VERSION 5.7 ;
DIVIDERCHAR "/" ;
BUSBITCHARS "[]" ;

VERSION 5.7 ;

BUSBITCHARS "[]" ;
DIVIDERCHAR "/" ;

UNITS
  TIME NANOSECONDS 1 ;
  CAPACITANCE PICOFARADS 1 ;
  RESISTANCE OHMS 1 ;
  DATABASE MICRONS 1000 ;
END UNITS

MANUFACTURINGGRID 0.005 ;

PROPERTYDEFINITIONS
  LAYER LEF58_TYPE STRING ;
END PROPERTYDEFINITIONS

# High density, single height
SITE obssite
  SYMMETRY Y ;
  CLASS CORE ;
  SIZE 0.56 BY 7.84 ;
END obssite


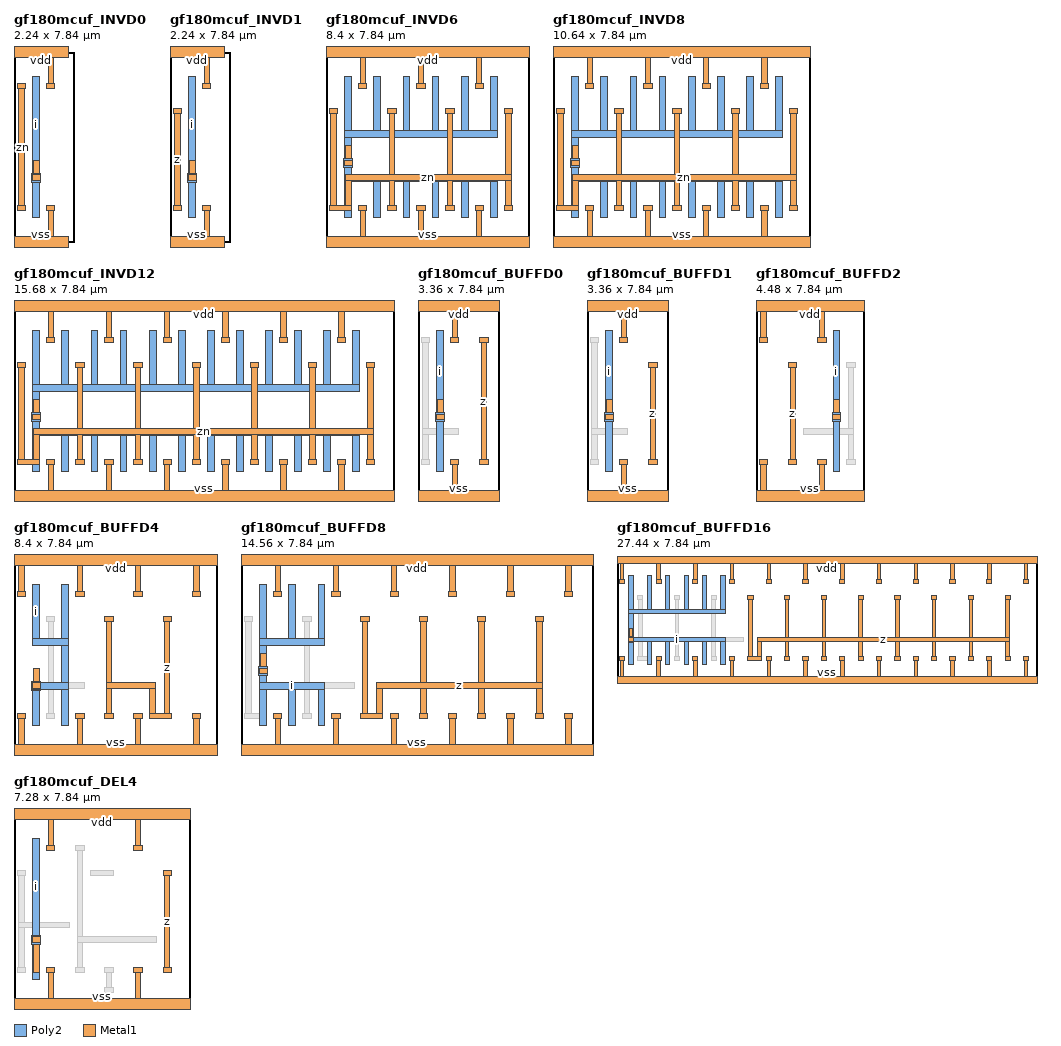
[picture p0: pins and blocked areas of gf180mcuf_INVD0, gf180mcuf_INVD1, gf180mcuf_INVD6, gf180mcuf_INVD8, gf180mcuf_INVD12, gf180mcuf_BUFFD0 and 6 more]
MACRO gf180mcuf_INVD0
  CLASS CORE ;
  FOREIGN gf180mcuf_INVD0 ;
  ORIGIN 0.000 0.000 ;
  SIZE 2.240 BY 7.840 ;
  SYMMETRY X Y R90 ;
  SITE obssite ;
  PIN i
    DIRECTION INPUT ;
    USE SIGNAL ;
    ANTENNAGATEAREA 0.308000 ;
    PORT
      LAYER Poly2 ;
        RECT 0.780 0.995 1.060 2.475 ;
        RECT 0.740 2.475 1.100 2.835 ;
        RECT 0.780 2.835 1.060 6.845 ;
      LAYER Metal1 ;
        RECT 0.750 2.540 1.090 2.770 ;
        RECT 0.805 2.770 1.035 3.370 ;
    END
  END i
  PIN vdd
    DIRECTION INOUT ;
    USE POWER ;
    SHAPE ABUTMENT ;
    PORT
      LAYER Metal1 ;
        RECT 1.350 6.330 1.690 6.560 ;
        RECT 1.405 6.560 1.635 7.610 ;
        RECT 0.000 7.610 2.240 8.070 ;
    END
  END vdd
  PIN vss
    DIRECTION INOUT ;
    USE GROUND ;
    SHAPE ABUTMENT ;
    PORT
      LAYER Metal1 ;
        RECT 0.000 -0.230 2.240 0.230 ;
        RECT 1.405 0.230 1.635 1.280 ;
        RECT 1.350 1.280 1.690 1.510 ;
    END
  END vss
  PIN zn
    DIRECTION OUTPUT ;
    USE SIGNAL ;
    ANTENNADIFFAREA 0.704000 ;
    PORT
      LAYER Metal1 ;
        RECT 0.150 1.280 0.490 1.510 ;
        RECT 0.205 1.510 0.435 6.330 ;
        RECT 0.150 6.330 0.490 6.560 ;
    END
  END zn
END gf180mcuf_INVD0

MACRO gf180mcuf_INVD1
  CLASS CORE ;
  FOREIGN gf180mcuf_INVD1 ;
  ORIGIN 0.000 0.000 ;
  SIZE 2.240 BY 7.840 ;
  SYMMETRY X Y R90 ;
  SITE obssite ;
  PIN z
    DIRECTION OUTPUT ;
    USE SIGNAL ;
    ANTENNADIFFAREA 1.408000 ;
    PORT
      LAYER Metal1 ;
        RECT 0.150 1.280 0.490 1.510 ;
        RECT 0.205 1.510 0.435 5.290 ;
        RECT 0.150 5.290 0.490 5.520 ;
    END
  END z
  PIN vdd
    DIRECTION INOUT ;
    USE POWER ;
    SHAPE ABUTMENT ;
    PORT
      LAYER Metal1 ;
        RECT 1.350 6.330 1.690 6.560 ;
        RECT 1.405 6.560 1.635 7.610 ;
        RECT 0.000 7.610 2.240 8.070 ;
    END
  END vdd
  PIN vss
    DIRECTION INOUT ;
    USE GROUND ;
    SHAPE ABUTMENT ;
    PORT
      LAYER Metal1 ;
        RECT 0.000 -0.230 2.240 0.230 ;
        RECT 1.405 0.230 1.635 1.280 ;
        RECT 1.350 1.280 1.690 1.510 ;
    END
  END vss
  PIN i
    DIRECTION INPUT ;
    USE SIGNAL ;
    ANTENNAGATEAREA 0.616000 ;
    PORT
      LAYER Poly2 ;
        RECT 0.780 0.995 1.060 2.475 ;
        RECT 0.740 2.475 1.100 2.835 ;
        RECT 0.780 2.835 1.060 6.845 ;
      LAYER Metal1 ;
        RECT 0.750 2.540 1.090 2.770 ;
        RECT 0.805 2.770 1.035 3.370 ;
    END
  END i
END gf180mcuf_INVD1

MACRO gf180mcuf_INVD6
  CLASS CORE ;
  FOREIGN gf180mcuf_INVD6 ;
  ORIGIN 0.000 0.000 ;
  SIZE 8.400 BY 7.840 ;
  SYMMETRY X Y R90 ;
  SITE obssite ;
  PIN i
    DIRECTION INPUT ;
    USE SIGNAL ;
    ANTENNAGATEAREA 3.696000 ;
    PORT
      LAYER Poly2 ;
        RECT 0.780 0.995 1.060 2.515 ;
        RECT 1.980 0.995 2.260 2.515 ;
        RECT 3.180 0.995 3.460 2.515 ;
        RECT 4.380 0.995 4.660 2.515 ;
        RECT 5.580 0.995 5.860 2.515 ;
        RECT 6.780 0.995 7.060 2.515 ;
        RECT 0.780 2.515 7.060 2.795 ;
        RECT 0.780 2.795 1.060 3.075 ;
        RECT 0.740 3.075 1.100 3.435 ;
        RECT 0.780 3.435 1.060 4.315 ;
        RECT 0.780 4.315 7.060 4.595 ;
        RECT 0.780 4.595 1.060 6.845 ;
        RECT 1.980 4.595 2.260 6.845 ;
        RECT 3.180 4.595 3.460 6.845 ;
        RECT 4.380 4.595 4.660 6.845 ;
        RECT 5.580 4.595 5.860 6.845 ;
        RECT 6.780 4.595 7.060 6.845 ;
      LAYER Metal1 ;
        RECT 0.750 3.140 1.090 3.370 ;
        RECT 0.805 3.370 1.035 3.970 ;
    END
  END i
  PIN vdd
    DIRECTION INOUT ;
    USE POWER ;
    SHAPE ABUTMENT ;
    PORT
      LAYER Metal1 ;
        RECT 1.350 6.330 1.690 6.560 ;
        RECT 3.750 6.330 4.090 6.560 ;
        RECT 6.150 6.330 6.490 6.560 ;
        RECT 1.405 6.560 1.635 7.610 ;
        RECT 3.805 6.560 4.035 7.610 ;
        RECT 6.205 6.560 6.435 7.610 ;
        RECT 0.000 7.610 8.400 8.070 ;
    END
  END vdd
  PIN vss
    DIRECTION INOUT ;
    USE GROUND ;
    SHAPE ABUTMENT ;
    PORT
      LAYER Metal1 ;
        RECT 0.000 -0.230 8.400 0.230 ;
        RECT 1.405 0.230 1.635 1.280 ;
        RECT 3.805 0.230 4.035 1.280 ;
        RECT 6.205 0.230 6.435 1.280 ;
        RECT 1.350 1.280 1.690 1.510 ;
        RECT 3.750 1.280 4.090 1.510 ;
        RECT 6.150 1.280 6.490 1.510 ;
    END
  END vss
  PIN zn
    DIRECTION OUTPUT ;
    USE SIGNAL ;
    ANTENNADIFFAREA 6.864000 ;
    PORT
      LAYER Metal1 ;
        RECT 0.150 1.280 1.035 1.510 ;
        RECT 2.550 1.280 2.890 1.510 ;
        RECT 4.950 1.280 5.290 1.510 ;
        RECT 7.350 1.280 7.690 1.510 ;
        RECT 0.205 1.510 0.435 5.290 ;
        RECT 0.805 1.510 1.035 2.540 ;
        RECT 2.605 1.510 2.835 2.540 ;
        RECT 5.005 1.510 5.235 2.540 ;
        RECT 7.405 1.510 7.635 2.540 ;
        RECT 0.805 2.540 7.635 2.770 ;
        RECT 2.605 2.770 2.835 5.290 ;
        RECT 5.005 2.770 5.235 5.290 ;
        RECT 7.405 2.770 7.635 5.290 ;
        RECT 0.150 5.290 0.490 5.520 ;
        RECT 2.550 5.290 2.890 5.520 ;
        RECT 4.950 5.290 5.290 5.520 ;
        RECT 7.350 5.290 7.690 5.520 ;
    END
  END zn
END gf180mcuf_INVD6

MACRO gf180mcuf_INVD8
  CLASS CORE ;
  FOREIGN gf180mcuf_INVD8 ;
  ORIGIN 0.000 0.000 ;
  SIZE 10.640 BY 7.840 ;
  SYMMETRY X Y R90 ;
  SITE obssite ;
  PIN i
    DIRECTION INPUT ;
    USE SIGNAL ;
    ANTENNAGATEAREA 4.928000 ;
    PORT
      LAYER Poly2 ;
        RECT 0.780 0.995 1.060 2.515 ;
        RECT 1.980 0.995 2.260 2.515 ;
        RECT 3.180 0.995 3.460 2.515 ;
        RECT 4.380 0.995 4.660 2.515 ;
        RECT 5.580 0.995 5.860 2.515 ;
        RECT 6.780 0.995 7.060 2.515 ;
        RECT 7.980 0.995 8.260 2.515 ;
        RECT 9.180 0.995 9.460 2.515 ;
        RECT 0.780 2.515 9.460 2.795 ;
        RECT 0.780 2.795 1.060 3.075 ;
        RECT 0.740 3.075 1.100 3.435 ;
        RECT 0.780 3.435 1.060 4.315 ;
        RECT 0.780 4.315 9.460 4.595 ;
        RECT 0.780 4.595 1.060 6.845 ;
        RECT 1.980 4.595 2.260 6.845 ;
        RECT 3.180 4.595 3.460 6.845 ;
        RECT 4.380 4.595 4.660 6.845 ;
        RECT 5.580 4.595 5.860 6.845 ;
        RECT 6.780 4.595 7.060 6.845 ;
        RECT 7.980 4.595 8.260 6.845 ;
        RECT 9.180 4.595 9.460 6.845 ;
      LAYER Metal1 ;
        RECT 0.750 3.140 1.090 3.370 ;
        RECT 0.805 3.370 1.035 3.970 ;
    END
  END i
  PIN vdd
    DIRECTION INOUT ;
    USE POWER ;
    SHAPE ABUTMENT ;
    PORT
      LAYER Metal1 ;
        RECT 1.350 6.330 1.690 6.560 ;
        RECT 3.750 6.330 4.090 6.560 ;
        RECT 6.150 6.330 6.490 6.560 ;
        RECT 8.550 6.330 8.890 6.560 ;
        RECT 1.405 6.560 1.635 7.610 ;
        RECT 3.805 6.560 4.035 7.610 ;
        RECT 6.205 6.560 6.435 7.610 ;
        RECT 8.605 6.560 8.835 7.610 ;
        RECT 0.000 7.610 10.640 8.070 ;
    END
  END vdd
  PIN vss
    DIRECTION INOUT ;
    USE GROUND ;
    SHAPE ABUTMENT ;
    PORT
      LAYER Metal1 ;
        RECT 0.000 -0.230 10.640 0.230 ;
        RECT 1.405 0.230 1.635 1.280 ;
        RECT 3.805 0.230 4.035 1.280 ;
        RECT 6.205 0.230 6.435 1.280 ;
        RECT 8.605 0.230 8.835 1.280 ;
        RECT 1.350 1.280 1.690 1.510 ;
        RECT 3.750 1.280 4.090 1.510 ;
        RECT 6.150 1.280 6.490 1.510 ;
        RECT 8.550 1.280 8.890 1.510 ;
    END
  END vss
  PIN zn
    DIRECTION OUTPUT ;
    USE SIGNAL ;
    ANTENNADIFFAREA 8.888000 ;
    PORT
      LAYER Metal1 ;
        RECT 0.150 1.280 1.035 1.510 ;
        RECT 2.550 1.280 2.890 1.510 ;
        RECT 4.950 1.280 5.290 1.510 ;
        RECT 7.350 1.280 7.690 1.510 ;
        RECT 9.750 1.280 10.090 1.510 ;
        RECT 0.205 1.510 0.435 5.290 ;
        RECT 0.805 1.510 1.035 2.540 ;
        RECT 2.605 1.510 2.835 2.540 ;
        RECT 5.005 1.510 5.235 2.540 ;
        RECT 7.405 1.510 7.635 2.540 ;
        RECT 9.805 1.510 10.035 2.540 ;
        RECT 0.805 2.540 10.035 2.770 ;
        RECT 2.605 2.770 2.835 5.290 ;
        RECT 5.005 2.770 5.235 5.290 ;
        RECT 7.405 2.770 7.635 5.290 ;
        RECT 9.805 2.770 10.035 5.290 ;
        RECT 0.150 5.290 0.490 5.520 ;
        RECT 2.550 5.290 2.890 5.520 ;
        RECT 4.950 5.290 5.290 5.520 ;
        RECT 7.350 5.290 7.690 5.520 ;
        RECT 9.750 5.290 10.090 5.520 ;
    END
  END zn
END gf180mcuf_INVD8

MACRO gf180mcuf_INVD12
  CLASS CORE ;
  FOREIGN gf180mcuf_INVD12 ;
  ORIGIN 0.000 0.000 ;
  SIZE 15.680 BY 7.840 ;
  SYMMETRY X Y R90 ;
  SITE obssite ;
  PIN i
    DIRECTION INPUT ;
    USE SIGNAL ;
    ANTENNAGATEAREA 7.392000 ;
    PORT
      LAYER Poly2 ;
        RECT 0.780 0.995 1.060 2.515 ;
        RECT 1.980 0.995 2.260 2.515 ;
        RECT 3.180 0.995 3.460 2.515 ;
        RECT 4.380 0.995 4.660 2.515 ;
        RECT 5.580 0.995 5.860 2.515 ;
        RECT 6.780 0.995 7.060 2.515 ;
        RECT 7.980 0.995 8.260 2.515 ;
        RECT 9.180 0.995 9.460 2.515 ;
        RECT 10.380 0.995 10.660 2.515 ;
        RECT 11.580 0.995 11.860 2.515 ;
        RECT 12.780 0.995 13.060 2.515 ;
        RECT 13.980 0.995 14.260 2.515 ;
        RECT 0.780 2.515 14.260 2.795 ;
        RECT 0.780 2.795 1.060 3.075 ;
        RECT 0.740 3.075 1.100 3.435 ;
        RECT 0.780 3.435 1.060 4.315 ;
        RECT 0.780 4.315 14.260 4.595 ;
        RECT 0.780 4.595 1.060 6.845 ;
        RECT 1.980 4.595 2.260 6.845 ;
        RECT 3.180 4.595 3.460 6.845 ;
        RECT 4.380 4.595 4.660 6.845 ;
        RECT 5.580 4.595 5.860 6.845 ;
        RECT 6.780 4.595 7.060 6.845 ;
        RECT 7.980 4.595 8.260 6.845 ;
        RECT 9.180 4.595 9.460 6.845 ;
        RECT 10.380 4.595 10.660 6.845 ;
        RECT 11.580 4.595 11.860 6.845 ;
        RECT 12.780 4.595 13.060 6.845 ;
        RECT 13.980 4.595 14.260 6.845 ;
      LAYER Metal1 ;
        RECT 0.750 3.140 1.090 3.370 ;
        RECT 0.805 3.370 1.035 3.970 ;
    END
  END i
  PIN vdd
    DIRECTION INOUT ;
    USE POWER ;
    SHAPE ABUTMENT ;
    PORT
      LAYER Metal1 ;
        RECT 1.350 6.330 1.690 6.560 ;
        RECT 3.750 6.330 4.090 6.560 ;
        RECT 6.150 6.330 6.490 6.560 ;
        RECT 8.550 6.330 8.890 6.560 ;
        RECT 10.950 6.330 11.290 6.560 ;
        RECT 13.350 6.330 13.690 6.560 ;
        RECT 1.405 6.560 1.635 7.610 ;
        RECT 3.805 6.560 4.035 7.610 ;
        RECT 6.205 6.560 6.435 7.610 ;
        RECT 8.605 6.560 8.835 7.610 ;
        RECT 11.005 6.560 11.235 7.610 ;
        RECT 13.405 6.560 13.635 7.610 ;
        RECT 0.000 7.610 15.680 8.070 ;
    END
  END vdd
  PIN vss
    DIRECTION INOUT ;
    USE GROUND ;
    SHAPE ABUTMENT ;
    PORT
      LAYER Metal1 ;
        RECT 0.000 -0.230 15.680 0.230 ;
        RECT 1.405 0.230 1.635 1.280 ;
        RECT 3.805 0.230 4.035 1.280 ;
        RECT 6.205 0.230 6.435 1.280 ;
        RECT 8.605 0.230 8.835 1.280 ;
        RECT 11.005 0.230 11.235 1.280 ;
        RECT 13.405 0.230 13.635 1.280 ;
        RECT 1.350 1.280 1.690 1.510 ;
        RECT 3.750 1.280 4.090 1.510 ;
        RECT 6.150 1.280 6.490 1.510 ;
        RECT 8.550 1.280 8.890 1.510 ;
        RECT 10.950 1.280 11.290 1.510 ;
        RECT 13.350 1.280 13.690 1.510 ;
    END
  END vss
  PIN zn
    DIRECTION OUTPUT ;
    USE SIGNAL ;
    ANTENNADIFFAREA 12.936000 ;
    PORT
      LAYER Metal1 ;
        RECT 0.150 1.280 1.035 1.510 ;
        RECT 2.550 1.280 2.890 1.510 ;
        RECT 4.950 1.280 5.290 1.510 ;
        RECT 7.350 1.280 7.690 1.510 ;
        RECT 9.750 1.280 10.090 1.510 ;
        RECT 12.150 1.280 12.490 1.510 ;
        RECT 14.550 1.280 14.890 1.510 ;
        RECT 0.205 1.510 0.435 5.290 ;
        RECT 0.805 1.510 1.035 2.540 ;
        RECT 2.605 1.510 2.835 2.540 ;
        RECT 5.005 1.510 5.235 2.540 ;
        RECT 7.405 1.510 7.635 2.540 ;
        RECT 9.805 1.510 10.035 2.540 ;
        RECT 12.205 1.510 12.435 2.540 ;
        RECT 14.605 1.510 14.835 2.540 ;
        RECT 0.805 2.540 14.835 2.770 ;
        RECT 2.605 2.770 2.835 5.290 ;
        RECT 5.005 2.770 5.235 5.290 ;
        RECT 7.405 2.770 7.635 5.290 ;
        RECT 9.805 2.770 10.035 5.290 ;
        RECT 12.205 2.770 12.435 5.290 ;
        RECT 14.605 2.770 14.835 5.290 ;
        RECT 0.150 5.290 0.490 5.520 ;
        RECT 2.550 5.290 2.890 5.520 ;
        RECT 4.950 5.290 5.290 5.520 ;
        RECT 7.350 5.290 7.690 5.520 ;
        RECT 9.750 5.290 10.090 5.520 ;
        RECT 12.150 5.290 12.490 5.520 ;
        RECT 14.550 5.290 14.890 5.520 ;
    END
  END zn
END gf180mcuf_INVD12

MACRO gf180mcuf_BUFFD0
  CLASS CORE ;
  FOREIGN gf180mcuf_BUFFD0 ;
  ORIGIN 0.000 0.000 ;
  SIZE 3.360 BY 7.840 ;
  SYMMETRY X Y R90 ;
  SITE obssite ;
  PIN i
    DIRECTION INPUT ;
    USE SIGNAL ;
    ANTENNAGATEAREA 0.193200 ;
    PORT
      LAYER Poly2 ;
        RECT 0.780 0.995 1.060 3.075 ;
        RECT 0.740 3.075 1.100 3.435 ;
        RECT 0.780 3.435 1.060 6.845 ;
      LAYER Metal1 ;
        RECT 0.750 3.140 1.090 3.370 ;
        RECT 0.805 3.370 1.035 3.970 ;
    END
  END i
  PIN vdd
    DIRECTION INOUT ;
    USE POWER ;
    SHAPE ABUTMENT ;
    PORT
      LAYER Metal1 ;
        RECT 1.350 6.330 1.690 6.560 ;
        RECT 1.405 6.560 1.635 7.610 ;
        RECT 0.000 7.610 3.360 8.070 ;
    END
  END vdd
  PIN vss
    DIRECTION INOUT ;
    USE GROUND ;
    SHAPE ABUTMENT ;
    PORT
      LAYER Metal1 ;
        RECT 0.000 -0.230 3.360 0.230 ;
        RECT 1.405 0.230 1.635 1.280 ;
        RECT 1.350 1.280 1.690 1.510 ;
    END
  END vss
  PIN z
    DIRECTION OUTPUT ;
    USE SIGNAL ;
    ANTENNADIFFAREA 0.646400 ;
    PORT
      LAYER Metal1 ;
        RECT 2.550 1.280 2.890 1.510 ;
        RECT 2.605 1.510 2.835 6.330 ;
        RECT 2.550 6.330 2.890 6.560 ;
    END
  END z
  OBS
    LAYER Metal1 ;
      RECT 0.150 1.280 0.490 1.510 ;
      RECT 0.205 1.510 0.435 2.540 ;
      RECT 0.205 2.540 1.690 2.770 ;
      RECT 0.205 2.770 0.435 6.330 ;
      RECT 0.150 6.330 0.490 6.560 ;
  END
END gf180mcuf_BUFFD0

MACRO gf180mcuf_BUFFD1
  CLASS CORE ;
  FOREIGN gf180mcuf_BUFFD1 ;
  ORIGIN 0.000 0.000 ;
  SIZE 3.360 BY 7.840 ;
  SYMMETRY X Y R90 ;
  SITE obssite ;
  PIN i
    DIRECTION INPUT ;
    USE SIGNAL ;
    ANTENNAGATEAREA 0.308000 ;
    PORT
      LAYER Poly2 ;
        RECT 0.780 0.995 1.060 3.075 ;
        RECT 0.740 3.075 1.100 3.435 ;
        RECT 0.780 3.435 1.060 6.845 ;
      LAYER Metal1 ;
        RECT 0.750 3.140 1.090 3.370 ;
        RECT 0.805 3.370 1.035 3.970 ;
    END
  END i
  PIN vdd
    DIRECTION INOUT ;
    USE POWER ;
    SHAPE ABUTMENT ;
    PORT
      LAYER Metal1 ;
        RECT 1.350 6.330 1.690 6.560 ;
        RECT 1.405 6.560 1.635 7.610 ;
        RECT 0.000 7.610 3.360 8.070 ;
    END
  END vdd
  PIN vss
    DIRECTION INOUT ;
    USE GROUND ;
    SHAPE ABUTMENT ;
    PORT
      LAYER Metal1 ;
        RECT 0.000 -0.230 3.360 0.230 ;
        RECT 1.405 0.230 1.635 1.280 ;
        RECT 1.350 1.280 1.690 1.510 ;
    END
  END vss
  PIN z
    DIRECTION OUTPUT ;
    USE SIGNAL ;
    ANTENNADIFFAREA 1.408000 ;
    PORT
      LAYER Metal1 ;
        RECT 2.550 1.280 2.890 1.510 ;
        RECT 2.605 1.510 2.835 5.290 ;
        RECT 2.550 5.290 2.890 5.520 ;
    END
  END z
  OBS
    LAYER Metal1 ;
      RECT 0.150 1.280 0.490 1.510 ;
      RECT 0.205 1.510 0.435 2.540 ;
      RECT 0.205 2.540 1.690 2.770 ;
      RECT 0.205 2.770 0.435 6.330 ;
      RECT 0.150 6.330 0.490 6.560 ;
  END
END gf180mcuf_BUFFD1

MACRO gf180mcuf_BUFFD2
  CLASS CORE ;
  FOREIGN gf180mcuf_BUFFD2 ;
  ORIGIN 0.000 0.000 ;
  SIZE 4.480 BY 7.840 ;
  SYMMETRY X Y R90 ;
  SITE obssite ;
  PIN i
    DIRECTION INPUT ;
    USE SIGNAL ;
    ANTENNAGATEAREA 0.616000 ;
    PORT
      LAYER Poly2 ;
        RECT 3.180 0.995 3.460 3.075 ;
        RECT 3.140 3.075 3.500 3.435 ;
        RECT 3.180 3.435 3.460 6.845 ;
      LAYER Metal1 ;
        RECT 3.150 3.140 3.490 3.370 ;
        RECT 3.205 3.370 3.435 3.970 ;
    END
  END i
  PIN vdd
    DIRECTION INOUT ;
    USE POWER ;
    SHAPE ABUTMENT ;
    PORT
      LAYER Metal1 ;
        RECT 0.150 6.330 0.490 6.560 ;
        RECT 2.550 6.330 2.890 6.560 ;
        RECT 0.205 6.560 0.435 7.610 ;
        RECT 2.605 6.560 2.835 7.610 ;
        RECT 0.000 7.610 4.480 8.070 ;
    END
  END vdd
  PIN vss
    DIRECTION INOUT ;
    USE GROUND ;
    SHAPE ABUTMENT ;
    PORT
      LAYER Metal1 ;
        RECT 0.000 -0.230 4.480 0.230 ;
        RECT 0.205 0.230 0.435 1.280 ;
        RECT 2.605 0.230 2.835 1.280 ;
        RECT 0.150 1.280 0.490 1.510 ;
        RECT 2.550 1.280 2.890 1.510 ;
    END
  END vss
  PIN z
    DIRECTION OUTPUT ;
    USE SIGNAL ;
    ANTENNADIFFAREA 2.024000 ;
    PORT
      LAYER Metal1 ;
        RECT 1.350 1.280 1.690 1.510 ;
        RECT 1.405 1.510 1.635 5.290 ;
        RECT 1.350 5.290 1.690 5.520 ;
    END
  END z
  OBS
    LAYER Metal1 ;
      RECT 3.750 1.280 4.090 1.510 ;
      RECT 3.805 1.510 4.035 2.540 ;
      RECT 1.950 2.540 4.035 2.770 ;
      RECT 3.805 2.770 4.035 5.290 ;
      RECT 3.750 5.290 4.090 5.520 ;
  END
END gf180mcuf_BUFFD2

MACRO gf180mcuf_BUFFD4
  CLASS CORE ;
  FOREIGN gf180mcuf_BUFFD4 ;
  ORIGIN 0.000 0.000 ;
  SIZE 8.400 BY 7.840 ;
  SYMMETRY X Y R90 ;
  SITE obssite ;
  PIN i
    DIRECTION INPUT ;
    USE SIGNAL ;
    ANTENNAGATEAREA 1.232000 ;
    PORT
      LAYER Poly2 ;
        RECT 0.780 0.995 1.060 2.475 ;
        RECT 1.980 0.995 2.260 2.515 ;
        RECT 0.740 2.475 1.100 2.515 ;
        RECT 0.740 2.515 2.260 2.795 ;
        RECT 0.740 2.795 1.100 2.835 ;
        RECT 1.980 2.795 2.260 4.315 ;
        RECT 0.780 4.315 2.260 4.595 ;
        RECT 0.780 4.595 1.060 6.845 ;
        RECT 1.980 4.595 2.260 6.845 ;
      LAYER Metal1 ;
        RECT 0.750 2.540 1.090 2.770 ;
        RECT 0.805 2.770 1.035 3.370 ;
    END
  END i
  PIN vdd
    DIRECTION INOUT ;
    USE POWER ;
    SHAPE ABUTMENT ;
    PORT
      LAYER Metal1 ;
        RECT 0.150 6.330 0.490 6.560 ;
        RECT 2.550 6.330 2.890 6.560 ;
        RECT 4.950 6.330 5.290 6.560 ;
        RECT 7.350 6.330 7.690 6.560 ;
        RECT 0.205 6.560 0.435 7.610 ;
        RECT 2.605 6.560 2.835 7.610 ;
        RECT 5.005 6.560 5.235 7.610 ;
        RECT 7.405 6.560 7.635 7.610 ;
        RECT 0.000 7.610 8.400 8.070 ;
    END
  END vdd
  PIN vss
    DIRECTION INOUT ;
    USE GROUND ;
    SHAPE ABUTMENT ;
    PORT
      LAYER Metal1 ;
        RECT 0.000 -0.230 8.400 0.230 ;
        RECT 0.205 0.230 0.435 1.280 ;
        RECT 2.605 0.230 2.835 1.280 ;
        RECT 5.005 0.230 5.235 1.280 ;
        RECT 7.405 0.230 7.635 1.280 ;
        RECT 0.150 1.280 0.490 1.510 ;
        RECT 2.550 1.280 2.890 1.510 ;
        RECT 4.950 1.280 5.290 1.510 ;
        RECT 7.350 1.280 7.690 1.510 ;
    END
  END vss
  PIN z
    DIRECTION OUTPUT ;
    USE SIGNAL ;
    ANTENNADIFFAREA 4.048000 ;
    PORT
      LAYER Metal1 ;
        RECT 3.750 1.280 4.090 1.510 ;
        RECT 5.605 1.280 6.490 1.510 ;
        RECT 3.805 1.510 4.035 2.540 ;
        RECT 5.605 1.510 5.835 2.540 ;
        RECT 6.205 1.510 6.435 5.290 ;
        RECT 3.805 2.540 5.835 2.770 ;
        RECT 3.805 2.770 4.035 5.290 ;
        RECT 3.750 5.290 4.090 5.520 ;
        RECT 6.150 5.290 6.490 5.520 ;
    END
  END z
  OBS
    LAYER Metal1 ;
      RECT 1.350 1.280 1.690 1.510 ;
      RECT 1.405 1.510 1.635 2.540 ;
      RECT 1.405 2.540 2.890 2.770 ;
      RECT 1.405 2.770 1.635 5.290 ;
      RECT 1.350 5.290 1.690 5.520 ;
  END
END gf180mcuf_BUFFD4

MACRO gf180mcuf_BUFFD8
  CLASS CORE ;
  FOREIGN gf180mcuf_BUFFD8 ;
  ORIGIN 0.000 0.000 ;
  SIZE 14.560 BY 7.840 ;
  SYMMETRY X Y R90 ;
  SITE obssite ;
  PIN i
    DIRECTION INPUT ;
    USE SIGNAL ;
    ANTENNAGATEAREA 1.645000 ;
    PORT
      LAYER Poly2 ;
        RECT 0.780 0.995 1.060 2.515 ;
        RECT 1.980 0.995 2.260 2.515 ;
        RECT 3.180 0.995 3.460 2.515 ;
        RECT 0.780 2.515 3.460 2.795 ;
        RECT 0.780 2.795 1.060 3.075 ;
        RECT 0.740 3.075 1.100 3.435 ;
        RECT 0.780 3.435 1.060 4.315 ;
        RECT 0.780 4.315 3.460 4.595 ;
        RECT 0.780 4.595 1.060 6.845 ;
        RECT 1.980 4.595 2.260 6.845 ;
        RECT 3.180 4.595 3.460 6.845 ;
      LAYER Metal1 ;
        RECT 0.750 3.140 1.090 3.370 ;
        RECT 0.805 3.370 1.035 3.970 ;
    END
  END i
  PIN vdd
    DIRECTION INOUT ;
    USE POWER ;
    SHAPE ABUTMENT ;
    PORT
      LAYER Metal1 ;
        RECT 1.350 6.330 1.690 6.560 ;
        RECT 3.750 6.330 4.090 6.560 ;
        RECT 6.150 6.330 6.490 6.560 ;
        RECT 8.550 6.330 8.890 6.560 ;
        RECT 10.950 6.330 11.290 6.560 ;
        RECT 13.350 6.330 13.690 6.560 ;
        RECT 1.405 6.560 1.635 7.610 ;
        RECT 3.805 6.560 4.035 7.610 ;
        RECT 6.205 6.560 6.435 7.610 ;
        RECT 8.605 6.560 8.835 7.610 ;
        RECT 11.005 6.560 11.235 7.610 ;
        RECT 13.405 6.560 13.635 7.610 ;
        RECT 0.000 7.610 14.560 8.070 ;
    END
  END vdd
  PIN vss
    DIRECTION INOUT ;
    USE GROUND ;
    SHAPE ABUTMENT ;
    PORT
      LAYER Metal1 ;
        RECT 0.000 -0.230 14.560 0.230 ;
        RECT 1.405 0.230 1.635 1.280 ;
        RECT 3.805 0.230 4.035 1.280 ;
        RECT 6.205 0.230 6.435 1.280 ;
        RECT 8.605 0.230 8.835 1.280 ;
        RECT 11.005 0.230 11.235 1.280 ;
        RECT 13.405 0.230 13.635 1.280 ;
        RECT 1.350 1.280 1.690 1.510 ;
        RECT 3.750 1.280 4.090 1.510 ;
        RECT 6.150 1.280 6.490 1.510 ;
        RECT 8.550 1.280 8.890 1.510 ;
        RECT 10.950 1.280 11.290 1.510 ;
        RECT 13.350 1.280 13.690 1.510 ;
    END
  END vss
  PIN z
    DIRECTION OUTPUT ;
    USE SIGNAL ;
    ANTENNADIFFAREA 8.096000 ;
    PORT
      LAYER Metal1 ;
        RECT 4.950 1.280 5.835 1.510 ;
        RECT 7.350 1.280 7.690 1.510 ;
        RECT 9.750 1.280 10.090 1.510 ;
        RECT 12.150 1.280 12.490 1.510 ;
        RECT 5.005 1.510 5.235 5.290 ;
        RECT 5.605 1.510 5.835 2.540 ;
        RECT 7.405 1.510 7.635 2.540 ;
        RECT 9.805 1.510 10.035 2.540 ;
        RECT 12.205 1.510 12.435 2.540 ;
        RECT 5.605 2.540 12.435 2.770 ;
        RECT 7.405 2.770 7.635 5.290 ;
        RECT 9.805 2.770 10.035 5.290 ;
        RECT 12.205 2.770 12.435 5.290 ;
        RECT 4.950 5.290 5.290 5.520 ;
        RECT 7.350 5.290 7.690 5.520 ;
        RECT 9.750 5.290 10.090 5.520 ;
        RECT 12.150 5.290 12.490 5.520 ;
    END
  END z
  OBS
    LAYER Metal1 ;
      RECT 0.150 1.280 1.035 1.510 ;
      RECT 2.550 1.280 2.890 1.510 ;
      RECT 0.205 1.510 0.435 5.290 ;
      RECT 0.805 1.510 1.035 2.540 ;
      RECT 2.605 1.510 2.835 2.540 ;
      RECT 0.805 2.540 4.690 2.770 ;
      RECT 2.605 2.770 2.835 5.290 ;
      RECT 0.150 5.290 0.490 5.520 ;
      RECT 2.550 5.290 2.890 5.520 ;
  END
END gf180mcuf_BUFFD8

MACRO gf180mcuf_BUFFD16
  CLASS CORE ;
  FOREIGN gf180mcuf_BUFFD16 ;
  ORIGIN 0.000 0.000 ;
  SIZE 27.440 BY 7.840 ;
  SYMMETRY X Y R90 ;
  SITE obssite ;
  PIN i
    DIRECTION INPUT ;
    USE SIGNAL ;
    ANTENNAGATEAREA 3.288600 ;
    PORT
      LAYER Poly2 ;
        RECT 0.780 0.995 1.060 2.475 ;
        RECT 1.980 0.995 2.260 2.515 ;
        RECT 3.180 0.995 3.460 2.515 ;
        RECT 4.380 0.995 4.660 2.515 ;
        RECT 5.580 0.995 5.860 2.515 ;
        RECT 6.780 0.995 7.060 2.515 ;
        RECT 0.740 2.475 1.100 2.515 ;
        RECT 0.740 2.515 7.060 2.795 ;
        RECT 0.740 2.795 1.100 2.835 ;
        RECT 0.780 2.835 1.060 4.315 ;
        RECT 0.780 4.315 7.060 4.595 ;
        RECT 0.780 4.595 1.060 6.845 ;
        RECT 1.980 4.595 2.260 6.845 ;
        RECT 3.180 4.595 3.460 6.845 ;
        RECT 4.380 4.595 4.660 6.845 ;
        RECT 5.580 4.595 5.860 6.845 ;
        RECT 6.780 4.595 7.060 6.845 ;
      LAYER Metal1 ;
        RECT 0.750 2.540 1.090 2.770 ;
        RECT 0.805 2.770 1.035 3.370 ;
    END
  END i
  PIN vdd
    DIRECTION INOUT ;
    USE POWER ;
    SHAPE ABUTMENT ;
    PORT
      LAYER Metal1 ;
        RECT 0.150 6.330 0.490 6.560 ;
        RECT 2.550 6.330 2.890 6.560 ;
        RECT 4.950 6.330 5.290 6.560 ;
        RECT 7.350 6.330 7.690 6.560 ;
        RECT 9.750 6.330 10.090 6.560 ;
        RECT 12.150 6.330 12.490 6.560 ;
        RECT 14.550 6.330 14.890 6.560 ;
        RECT 16.950 6.330 17.290 6.560 ;
        RECT 19.350 6.330 19.690 6.560 ;
        RECT 21.750 6.330 22.090 6.560 ;
        RECT 24.150 6.330 24.490 6.560 ;
        RECT 26.550 6.330 26.890 6.560 ;
        RECT 0.205 6.560 0.435 7.610 ;
        RECT 2.605 6.560 2.835 7.610 ;
        RECT 5.005 6.560 5.235 7.610 ;
        RECT 7.405 6.560 7.635 7.610 ;
        RECT 9.805 6.560 10.035 7.610 ;
        RECT 12.205 6.560 12.435 7.610 ;
        RECT 14.605 6.560 14.835 7.610 ;
        RECT 17.005 6.560 17.235 7.610 ;
        RECT 19.405 6.560 19.635 7.610 ;
        RECT 21.805 6.560 22.035 7.610 ;
        RECT 24.205 6.560 24.435 7.610 ;
        RECT 26.605 6.560 26.835 7.610 ;
        RECT 0.000 7.610 27.440 8.070 ;
    END
  END vdd
  PIN vss
    DIRECTION INOUT ;
    USE GROUND ;
    SHAPE ABUTMENT ;
    PORT
      LAYER Metal1 ;
        RECT 0.000 -0.230 27.440 0.230 ;
        RECT 0.205 0.230 0.435 1.280 ;
        RECT 2.605 0.230 2.835 1.280 ;
        RECT 5.005 0.230 5.235 1.280 ;
        RECT 7.405 0.230 7.635 1.280 ;
        RECT 9.805 0.230 10.035 1.280 ;
        RECT 12.205 0.230 12.435 1.280 ;
        RECT 14.605 0.230 14.835 1.280 ;
        RECT 17.005 0.230 17.235 1.280 ;
        RECT 19.405 0.230 19.635 1.280 ;
        RECT 21.805 0.230 22.035 1.280 ;
        RECT 24.205 0.230 24.435 1.280 ;
        RECT 26.605 0.230 26.835 1.280 ;
        RECT 0.150 1.280 0.490 1.510 ;
        RECT 2.550 1.280 2.890 1.510 ;
        RECT 4.950 1.280 5.290 1.510 ;
        RECT 7.350 1.280 7.690 1.510 ;
        RECT 9.750 1.280 10.090 1.510 ;
        RECT 12.150 1.280 12.490 1.510 ;
        RECT 14.550 1.280 14.890 1.510 ;
        RECT 16.950 1.280 17.290 1.510 ;
        RECT 19.350 1.280 19.690 1.510 ;
        RECT 21.750 1.280 22.090 1.510 ;
        RECT 24.150 1.280 24.490 1.510 ;
        RECT 26.550 1.280 26.890 1.510 ;
    END
  END vss
  PIN z
    DIRECTION OUTPUT ;
    USE SIGNAL ;
    ANTENNADIFFAREA 16.192000 ;
    PORT
      LAYER Metal1 ;
        RECT 8.550 1.280 9.435 1.510 ;
        RECT 10.950 1.280 11.290 1.510 ;
        RECT 13.350 1.280 13.690 1.510 ;
        RECT 15.750 1.280 16.090 1.510 ;
        RECT 18.150 1.280 18.490 1.510 ;
        RECT 20.550 1.280 20.890 1.510 ;
        RECT 22.950 1.280 23.290 1.510 ;
        RECT 25.350 1.280 25.690 1.510 ;
        RECT 8.605 1.510 8.835 5.290 ;
        RECT 9.205 1.510 9.435 2.540 ;
        RECT 11.005 1.510 11.235 2.540 ;
        RECT 13.405 1.510 13.635 2.540 ;
        RECT 15.805 1.510 16.035 2.540 ;
        RECT 18.205 1.510 18.435 2.540 ;
        RECT 20.605 1.510 20.835 2.540 ;
        RECT 23.005 1.510 23.235 2.540 ;
        RECT 25.405 1.510 25.635 2.540 ;
        RECT 9.205 2.540 25.635 2.770 ;
        RECT 11.005 2.770 11.235 5.290 ;
        RECT 13.405 2.770 13.635 5.290 ;
        RECT 15.805 2.770 16.035 5.290 ;
        RECT 18.205 2.770 18.435 5.290 ;
        RECT 20.605 2.770 20.835 5.290 ;
        RECT 23.005 2.770 23.235 5.290 ;
        RECT 25.405 2.770 25.635 5.290 ;
        RECT 8.550 5.290 8.890 5.520 ;
        RECT 10.950 5.290 11.290 5.520 ;
        RECT 13.350 5.290 13.690 5.520 ;
        RECT 15.750 5.290 16.090 5.520 ;
        RECT 18.150 5.290 18.490 5.520 ;
        RECT 20.550 5.290 20.890 5.520 ;
        RECT 22.950 5.290 23.290 5.520 ;
        RECT 25.350 5.290 25.690 5.520 ;
    END
  END z
  OBS
    LAYER Metal1 ;
      RECT 1.350 1.280 2.235 1.510 ;
      RECT 3.750 1.280 4.090 1.510 ;
      RECT 6.150 1.280 6.490 1.510 ;
      RECT 1.405 1.510 1.635 5.290 ;
      RECT 2.005 1.510 2.235 2.540 ;
      RECT 3.805 1.510 4.035 2.540 ;
      RECT 6.205 1.510 6.435 2.540 ;
      RECT 2.005 2.540 8.290 2.770 ;
      RECT 3.805 2.770 4.035 5.290 ;
      RECT 6.205 2.770 6.435 5.290 ;
      RECT 1.350 5.290 1.690 5.520 ;
      RECT 3.750 5.290 4.090 5.520 ;
      RECT 6.150 5.290 6.490 5.520 ;
  END
END gf180mcuf_BUFFD16

MACRO gf180mcuf_DEL4
  CLASS CORE ;
  FOREIGN gf180mcuf_DEL4 ;
  ORIGIN 0.000 0.000 ;
  SIZE 7.280 BY 7.840 ;
  SYMMETRY X Y R90 ;
  SITE obssite ;
  PIN i
    DIRECTION INPUT ;
    USE SIGNAL ;
    ANTENNAGATEAREA 0.616000 ;
    PORT
      LAYER Poly2 ;
        RECT 0.780 0.995 1.060 2.475 ;
        RECT 0.740 2.475 1.100 2.835 ;
        RECT 0.780 2.835 1.060 6.845 ;
      LAYER Metal1 ;
        RECT 0.805 1.280 1.035 2.540 ;
        RECT 0.750 2.540 1.090 2.770 ;
    END
  END i
  PIN vdd
    DIRECTION INOUT ;
    USE POWER ;
    SHAPE ABUTMENT ;
    PORT
      LAYER Metal1 ;
        RECT 1.350 6.330 1.690 6.560 ;
        RECT 4.950 6.330 5.290 6.560 ;
        RECT 1.405 6.560 1.635 7.610 ;
        RECT 5.005 6.560 5.235 7.610 ;
        RECT 0.000 7.610 7.280 8.070 ;
    END
  END vdd
  PIN vss
    DIRECTION INOUT ;
    USE GROUND ;
    SHAPE ABUTMENT ;
    PORT
      LAYER Metal1 ;
        RECT 0.000 -0.230 7.280 0.230 ;
        RECT 1.405 0.230 1.635 1.280 ;
        RECT 5.005 0.230 5.235 1.280 ;
        RECT 1.350 1.280 1.690 1.510 ;
        RECT 4.950 1.280 5.290 1.510 ;
    END
  END vss
  PIN z
    DIRECTION OUTPUT ;
    USE SIGNAL ;
    ANTENNADIFFAREA 1.408000 ;
    PORT
      LAYER Metal1 ;
        RECT 6.150 1.280 6.490 1.510 ;
        RECT 6.205 1.510 6.435 5.290 ;
        RECT 6.150 5.290 6.490 5.520 ;
    END
  END z
  OBS
    LAYER Metal1 ;
      RECT 3.750 0.460 4.090 0.690 ;
      RECT 3.805 0.690 4.035 1.280 ;
      RECT 0.150 1.280 0.490 1.510 ;
      RECT 2.550 1.280 2.890 1.510 ;
      RECT 3.750 1.280 4.090 1.510 ;
      RECT 0.205 1.510 0.435 3.140 ;
      RECT 2.605 1.510 2.835 2.540 ;
      RECT 2.605 2.540 5.890 2.770 ;
      RECT 2.605 2.770 2.835 6.330 ;
      RECT 0.205 3.140 2.290 3.370 ;
      RECT 0.205 3.370 0.435 5.290 ;
      RECT 0.150 5.290 0.490 5.520 ;
      RECT 3.150 5.290 4.090 5.520 ;
      RECT 2.550 6.330 2.890 6.560 ;
  END
END gf180mcuf_DEL4

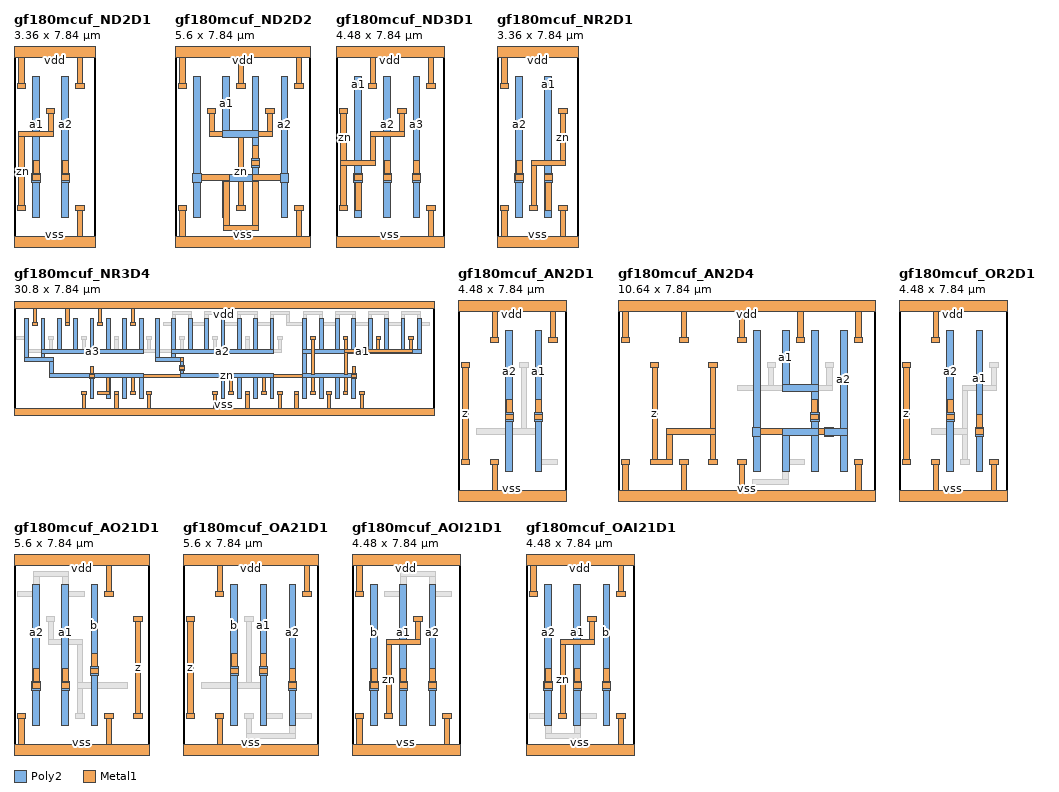
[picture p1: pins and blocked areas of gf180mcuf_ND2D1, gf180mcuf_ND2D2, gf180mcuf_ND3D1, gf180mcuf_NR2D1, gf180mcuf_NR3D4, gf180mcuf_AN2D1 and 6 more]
MACRO gf180mcuf_ND2D1
  CLASS CORE ;
  FOREIGN gf180mcuf_ND2D1 ;
  ORIGIN 0.000 0.000 ;
  SIZE 3.360 BY 7.840 ;
  SYMMETRY X Y R90 ;
  SITE obssite ;
  PIN a1
    DIRECTION INPUT ;
    USE SIGNAL ;
    ANTENNAGATEAREA 0.616000 ;
    PORT
      LAYER Poly2 ;
        RECT 0.780 0.995 1.060 2.475 ;
        RECT 0.740 2.475 1.100 2.835 ;
        RECT 0.780 2.835 1.060 6.845 ;
      LAYER Metal1 ;
        RECT 0.750 2.540 1.090 2.770 ;
        RECT 0.805 2.770 1.035 3.370 ;
    END
  END a1
  PIN a2
    DIRECTION INPUT ;
    USE SIGNAL ;
    ANTENNAGATEAREA 0.616000 ;
    PORT
      LAYER Poly2 ;
        RECT 1.980 0.995 2.260 2.475 ;
        RECT 1.940 2.475 2.300 2.835 ;
        RECT 1.980 2.835 2.260 6.845 ;
      LAYER Metal1 ;
        RECT 1.950 2.540 2.290 2.770 ;
        RECT 2.005 2.770 2.235 3.370 ;
    END
  END a2
  PIN vdd
    DIRECTION INOUT ;
    USE POWER ;
    SHAPE ABUTMENT ;
    PORT
      LAYER Metal1 ;
        RECT 0.150 6.330 0.490 6.560 ;
        RECT 2.550 6.330 2.890 6.560 ;
        RECT 0.205 6.560 0.435 7.610 ;
        RECT 2.605 6.560 2.835 7.610 ;
        RECT 0.000 7.610 3.360 8.070 ;
    END
  END vdd
  PIN vss
    DIRECTION INOUT ;
    USE GROUND ;
    SHAPE ABUTMENT ;
    PORT
      LAYER Metal1 ;
        RECT 0.000 -0.230 3.360 0.230 ;
        RECT 2.605 0.230 2.835 1.280 ;
        RECT 2.550 1.280 2.890 1.510 ;
    END
  END vss
  PIN zn
    DIRECTION OUTPUT ;
    USE SIGNAL ;
    ANTENNADIFFAREA 1.800000 ;
    PORT
      LAYER Metal1 ;
        RECT 0.150 1.280 0.490 1.510 ;
        RECT 0.205 1.510 0.435 4.340 ;
        RECT 0.205 4.340 1.635 4.570 ;
        RECT 1.405 4.570 1.635 5.290 ;
        RECT 1.350 5.290 1.690 5.520 ;
    END
  END zn
END gf180mcuf_ND2D1

MACRO gf180mcuf_ND2D2
  CLASS CORE ;
  FOREIGN gf180mcuf_ND2D2 ;
  ORIGIN 0.000 0.000 ;
  SIZE 5.600 BY 7.840 ;
  SYMMETRY X Y R90 ;
  SITE obssite ;
  PIN a1
    DIRECTION INPUT ;
    USE SIGNAL ;
    ANTENNAGATEAREA 1.232000 ;
    PORT
      LAYER Poly2 ;
        RECT 1.980 0.995 2.260 2.515 ;
        RECT 3.180 0.995 3.460 2.515 ;
        RECT 1.980 2.515 3.460 2.795 ;
        RECT 3.180 2.795 3.460 3.075 ;
        RECT 3.140 3.075 3.500 3.435 ;
        RECT 3.180 3.435 3.460 4.315 ;
        RECT 1.980 4.315 3.460 4.595 ;
        RECT 1.980 4.595 2.260 6.845 ;
        RECT 3.180 4.595 3.460 6.845 ;
      LAYER Metal1 ;
        RECT 3.150 3.140 3.490 3.370 ;
        RECT 3.205 3.370 3.435 3.970 ;
    END
  END a1
  PIN a2
    DIRECTION INPUT ;
    USE SIGNAL ;
    ANTENNAGATEAREA 1.232000 ;
    PORT
      LAYER Poly2 ;
        RECT 0.780 0.995 1.060 2.475 ;
        RECT 4.380 0.995 4.660 2.475 ;
        RECT 0.740 2.475 1.100 2.835 ;
        RECT 4.340 2.475 4.700 2.835 ;
        RECT 0.780 2.835 1.060 6.845 ;
        RECT 4.380 2.835 4.660 6.845 ;
      LAYER Metal1 ;
        RECT 2.005 0.460 3.435 0.690 ;
        RECT 2.005 0.690 2.235 2.540 ;
        RECT 3.205 0.690 3.435 2.540 ;
        RECT 0.750 2.540 2.235 2.770 ;
        RECT 3.205 2.540 4.690 2.770 ;
    END
  END a2
  PIN vdd
    DIRECTION INOUT ;
    USE POWER ;
    SHAPE ABUTMENT ;
    PORT
      LAYER Metal1 ;
        RECT 0.150 6.330 0.490 6.560 ;
        RECT 2.550 6.330 2.890 6.560 ;
        RECT 4.950 6.330 5.290 6.560 ;
        RECT 0.205 6.560 0.435 7.610 ;
        RECT 2.605 6.560 2.835 7.610 ;
        RECT 5.005 6.560 5.235 7.610 ;
        RECT 0.000 7.610 5.600 8.070 ;
    END
  END vdd
  PIN vss
    DIRECTION INOUT ;
    USE GROUND ;
    SHAPE ABUTMENT ;
    PORT
      LAYER Metal1 ;
        RECT 0.000 -0.230 5.600 0.230 ;
        RECT 0.205 0.230 0.435 1.280 ;
        RECT 5.005 0.230 5.235 1.280 ;
        RECT 0.150 1.280 0.490 1.510 ;
        RECT 4.950 1.280 5.290 1.510 ;
    END
  END vss
  PIN zn
    DIRECTION OUTPUT ;
    USE SIGNAL ;
    ANTENNADIFFAREA 3.312000 ;
    PORT
      LAYER Metal1 ;
        RECT 2.550 1.280 2.890 1.510 ;
        RECT 2.605 1.510 2.835 4.340 ;
        RECT 1.405 4.340 4.035 4.570 ;
        RECT 1.405 4.570 1.635 5.290 ;
        RECT 3.805 4.570 4.035 5.290 ;
        RECT 1.350 5.290 1.690 5.520 ;
        RECT 3.750 5.290 4.090 5.520 ;
    END
  END zn
END gf180mcuf_ND2D2

MACRO gf180mcuf_ND3D1
  CLASS CORE ;
  FOREIGN gf180mcuf_ND3D1 ;
  ORIGIN 0.000 0.000 ;
  SIZE 4.480 BY 7.840 ;
  SYMMETRY X Y R90 ;
  SITE obssite ;
  PIN a1
    DIRECTION INPUT ;
    USE SIGNAL ;
    ANTENNAGATEAREA 0.616000 ;
    PORT
      LAYER Poly2 ;
        RECT 0.780 0.995 1.060 2.475 ;
        RECT 0.740 2.475 1.100 2.835 ;
        RECT 0.780 2.835 1.060 6.845 ;
      LAYER Metal1 ;
        RECT 0.805 1.280 1.035 2.540 ;
        RECT 0.750 2.540 1.090 2.770 ;
    END
  END a1
  PIN a2
    DIRECTION INPUT ;
    USE SIGNAL ;
    ANTENNAGATEAREA 0.616000 ;
    PORT
      LAYER Poly2 ;
        RECT 1.980 0.995 2.260 2.475 ;
        RECT 1.940 2.475 2.300 2.835 ;
        RECT 1.980 2.835 2.260 6.845 ;
      LAYER Metal1 ;
        RECT 1.950 2.540 2.290 2.770 ;
        RECT 2.005 2.770 2.235 3.370 ;
    END
  END a2
  PIN a3
    DIRECTION INPUT ;
    USE SIGNAL ;
    ANTENNAGATEAREA 0.616000 ;
    PORT
      LAYER Poly2 ;
        RECT 3.180 0.995 3.460 2.475 ;
        RECT 3.140 2.475 3.500 2.835 ;
        RECT 3.180 2.835 3.460 6.845 ;
      LAYER Metal1 ;
        RECT 3.150 2.540 3.490 2.770 ;
        RECT 3.205 2.770 3.435 3.370 ;
    END
  END a3
  PIN vdd
    DIRECTION INOUT ;
    USE POWER ;
    SHAPE ABUTMENT ;
    PORT
      LAYER Metal1 ;
        RECT 1.350 6.330 1.690 6.560 ;
        RECT 3.750 6.330 4.090 6.560 ;
        RECT 1.405 6.560 1.635 7.610 ;
        RECT 3.805 6.560 4.035 7.610 ;
        RECT 0.000 7.610 4.480 8.070 ;
    END
  END vdd
  PIN vss
    DIRECTION INOUT ;
    USE GROUND ;
    SHAPE ABUTMENT ;
    PORT
      LAYER Metal1 ;
        RECT 0.000 -0.230 4.480 0.230 ;
        RECT 3.805 0.230 4.035 1.280 ;
        RECT 3.750 1.280 4.090 1.510 ;
    END
  END vss
  PIN zn
    DIRECTION OUTPUT ;
    USE SIGNAL ;
    ANTENNADIFFAREA 2.696000 ;
    PORT
      LAYER Metal1 ;
        RECT 0.150 1.280 0.490 1.510 ;
        RECT 0.205 1.510 0.435 3.140 ;
        RECT 0.205 3.140 1.635 3.370 ;
        RECT 0.205 3.370 0.435 5.290 ;
        RECT 1.405 3.370 1.635 4.340 ;
        RECT 1.405 4.340 2.835 4.570 ;
        RECT 2.605 4.570 2.835 5.290 ;
        RECT 0.150 5.290 0.490 5.520 ;
        RECT 2.550 5.290 2.890 5.520 ;
    END
  END zn
END gf180mcuf_ND3D1

MACRO gf180mcuf_NR2D1
  CLASS CORE ;
  FOREIGN gf180mcuf_NR2D1 ;
  ORIGIN 0.000 0.000 ;
  SIZE 3.360 BY 7.840 ;
  SYMMETRY X Y R90 ;
  SITE obssite ;
  PIN a1
    DIRECTION INPUT ;
    USE SIGNAL ;
    ANTENNAGATEAREA 0.616000 ;
    PORT
      LAYER Poly2 ;
        RECT 1.980 0.995 2.260 2.475 ;
        RECT 1.940 2.475 2.300 2.835 ;
        RECT 1.980 2.835 2.260 6.845 ;
      LAYER Metal1 ;
        RECT 2.005 1.280 2.235 2.540 ;
        RECT 1.950 2.540 2.290 2.770 ;
    END
  END a1
  PIN a2
    DIRECTION INPUT ;
    USE SIGNAL ;
    ANTENNAGATEAREA 0.616000 ;
    PORT
      LAYER Poly2 ;
        RECT 0.780 0.995 1.060 2.475 ;
        RECT 0.740 2.475 1.100 2.835 ;
        RECT 0.780 2.835 1.060 6.845 ;
      LAYER Metal1 ;
        RECT 0.750 2.540 1.090 2.770 ;
        RECT 0.805 2.770 1.035 3.370 ;
    END
  END a2
  PIN vdd
    DIRECTION INOUT ;
    USE POWER ;
    SHAPE ABUTMENT ;
    PORT
      LAYER Metal1 ;
        RECT 0.150 6.330 0.490 6.560 ;
        RECT 0.205 6.560 0.435 7.610 ;
        RECT 0.000 7.610 3.360 8.070 ;
    END
  END vdd
  PIN vss
    DIRECTION INOUT ;
    USE GROUND ;
    SHAPE ABUTMENT ;
    PORT
      LAYER Metal1 ;
        RECT 0.000 -0.230 3.360 0.230 ;
        RECT 0.205 0.230 0.435 1.280 ;
        RECT 2.605 0.230 2.835 1.280 ;
        RECT 0.150 1.280 0.490 1.510 ;
        RECT 2.550 1.280 2.890 1.510 ;
    END
  END vss
  PIN zn
    DIRECTION OUTPUT ;
    USE SIGNAL ;
    ANTENNADIFFAREA 1.632000 ;
    PORT
      LAYER Metal1 ;
        RECT 1.350 1.280 1.690 1.510 ;
        RECT 1.405 1.510 1.635 3.140 ;
        RECT 1.405 3.140 2.835 3.370 ;
        RECT 2.605 3.370 2.835 5.290 ;
        RECT 2.550 5.290 2.890 5.520 ;
    END
  END zn
END gf180mcuf_NR2D1

MACRO gf180mcuf_NR3D4
  CLASS CORE ;
  FOREIGN gf180mcuf_NR3D4 ;
  ORIGIN 0.000 0.000 ;
  SIZE 30.800 BY 7.840 ;
  SYMMETRY X Y R90 ;
  SITE obssite ;
  PIN a1
    DIRECTION INPUT ;
    USE SIGNAL ;
    ANTENNAGATEAREA 4.032000 ;
    PORT
      LAYER Poly2 ;
        RECT 21.180 0.995 21.460 2.515 ;
        RECT 22.380 0.995 22.660 2.515 ;
        RECT 23.580 0.995 23.860 2.515 ;
        RECT 24.780 0.995 25.060 2.475 ;
        RECT 24.740 2.475 25.100 2.515 ;
        RECT 21.180 2.515 25.100 2.795 ;
        RECT 21.180 2.795 21.460 4.315 ;
        RECT 24.740 2.795 25.100 2.835 ;
        RECT 21.180 4.315 29.860 4.595 ;
        RECT 21.180 4.595 21.460 6.845 ;
        RECT 22.380 4.595 22.660 6.845 ;
        RECT 23.580 4.595 23.860 6.845 ;
        RECT 24.780 4.595 25.060 6.845 ;
        RECT 25.980 4.595 26.260 6.845 ;
        RECT 27.180 4.595 27.460 6.845 ;
        RECT 28.380 4.595 28.660 6.845 ;
        RECT 29.580 4.595 29.860 6.845 ;
      LAYER Metal1 ;
        RECT 24.750 2.540 25.090 2.770 ;
        RECT 24.805 2.770 25.035 3.370 ;
    END
  END a1
  PIN a2
    DIRECTION INPUT ;
    USE SIGNAL ;
    ANTENNAGATEAREA 4.032000 ;
    PORT
      LAYER Poly2 ;
        RECT 15.180 0.995 15.460 2.515 ;
        RECT 16.380 0.995 16.660 2.515 ;
        RECT 17.580 0.995 17.860 2.515 ;
        RECT 18.780 0.995 19.060 2.515 ;
        RECT 12.180 2.515 19.060 2.795 ;
        RECT 12.180 2.795 12.460 3.075 ;
        RECT 12.140 3.075 12.500 3.435 ;
        RECT 12.180 3.435 12.460 3.715 ;
        RECT 10.380 3.715 12.460 3.995 ;
        RECT 10.380 3.995 10.660 6.845 ;
        RECT 11.580 3.995 11.860 4.315 ;
        RECT 11.580 4.315 19.060 4.595 ;
        RECT 11.580 4.595 11.860 6.845 ;
        RECT 12.780 4.595 13.060 6.845 ;
        RECT 13.980 4.595 14.260 6.845 ;
        RECT 15.180 4.595 15.460 6.845 ;
        RECT 16.380 4.595 16.660 6.845 ;
        RECT 17.580 4.595 17.860 6.845 ;
        RECT 18.780 4.595 19.060 6.845 ;
      LAYER Metal1 ;
        RECT 12.150 3.140 12.490 3.370 ;
        RECT 12.205 3.370 12.435 3.970 ;
    END
  END a2
  PIN a3
    DIRECTION INPUT ;
    USE SIGNAL ;
    ANTENNAGATEAREA 4.032000 ;
    PORT
      LAYER Poly2 ;
        RECT 5.580 0.995 5.860 2.475 ;
        RECT 6.780 0.995 7.060 2.515 ;
        RECT 7.980 0.995 8.260 2.515 ;
        RECT 9.180 0.995 9.460 2.515 ;
        RECT 5.540 2.475 5.900 2.515 ;
        RECT 2.580 2.515 9.460 2.795 ;
        RECT 2.580 2.795 2.860 3.715 ;
        RECT 5.540 2.795 5.900 2.835 ;
        RECT 0.780 3.715 2.860 3.995 ;
        RECT 0.780 3.995 1.060 6.845 ;
        RECT 1.980 3.995 2.260 4.315 ;
        RECT 1.980 4.315 9.460 4.595 ;
        RECT 1.980 4.595 2.260 6.845 ;
        RECT 3.180 4.595 3.460 6.845 ;
        RECT 4.380 4.595 4.660 6.845 ;
        RECT 5.580 4.595 5.860 6.845 ;
        RECT 6.780 4.595 7.060 6.845 ;
        RECT 7.980 4.595 8.260 6.845 ;
        RECT 9.180 4.595 9.460 6.845 ;
      LAYER Metal1 ;
        RECT 5.550 2.540 5.890 2.770 ;
        RECT 5.605 2.770 5.835 3.370 ;
    END
  END a3
  PIN vdd
    DIRECTION INOUT ;
    USE POWER ;
    SHAPE ABUTMENT ;
    PORT
      LAYER Metal1 ;
        RECT 1.350 6.330 1.690 6.560 ;
        RECT 3.750 6.330 4.090 6.560 ;
        RECT 6.150 6.330 6.490 6.560 ;
        RECT 8.550 6.330 8.890 6.560 ;
        RECT 1.405 6.560 1.635 7.610 ;
        RECT 3.805 6.560 4.035 7.610 ;
        RECT 6.205 6.560 6.435 7.610 ;
        RECT 8.605 6.560 8.835 7.610 ;
        RECT 0.000 7.610 30.800 8.070 ;
    END
  END vdd
  PIN vss
    DIRECTION INOUT ;
    USE GROUND ;
    SHAPE ABUTMENT ;
    PORT
      LAYER Metal1 ;
        RECT 0.000 -0.230 30.800 0.230 ;
        RECT 5.005 0.230 5.235 1.280 ;
        RECT 7.405 0.230 7.635 1.280 ;
        RECT 9.805 0.230 10.035 1.280 ;
        RECT 14.605 0.230 14.835 1.280 ;
        RECT 17.005 0.230 17.235 1.280 ;
        RECT 19.405 0.230 19.635 1.280 ;
        RECT 20.605 0.230 20.835 1.280 ;
        RECT 23.005 0.230 23.235 1.280 ;
        RECT 25.405 0.230 25.635 1.280 ;
        RECT 4.950 1.280 5.290 1.510 ;
        RECT 7.350 1.280 7.690 1.510 ;
        RECT 9.750 1.280 10.090 1.510 ;
        RECT 14.550 1.280 14.890 1.510 ;
        RECT 16.950 1.280 17.290 1.510 ;
        RECT 19.350 1.280 19.690 1.510 ;
        RECT 20.550 1.280 20.890 1.510 ;
        RECT 22.950 1.280 23.290 1.510 ;
        RECT 25.350 1.280 25.690 1.510 ;
    END
  END vss
  PIN zn
    DIRECTION OUTPUT ;
    USE SIGNAL ;
    ANTENNADIFFAREA 9.568000 ;
    PORT
      LAYER Metal1 ;
        RECT 6.150 1.280 7.035 1.510 ;
        RECT 8.550 1.280 8.890 1.510 ;
        RECT 15.750 1.280 16.090 1.510 ;
        RECT 18.150 1.280 18.490 1.510 ;
        RECT 21.750 1.280 22.090 1.510 ;
        RECT 24.150 1.280 24.490 1.510 ;
        RECT 6.805 1.510 7.035 2.540 ;
        RECT 8.605 1.510 8.835 2.540 ;
        RECT 15.805 1.510 16.035 2.540 ;
        RECT 18.205 1.510 18.435 2.540 ;
        RECT 21.805 1.510 22.035 2.540 ;
        RECT 24.205 1.510 24.435 2.540 ;
        RECT 6.805 2.540 24.435 2.770 ;
        RECT 21.805 2.770 22.035 5.290 ;
        RECT 24.205 2.770 24.435 4.340 ;
        RECT 24.205 4.340 29.235 4.570 ;
        RECT 24.205 4.570 24.435 5.290 ;
        RECT 26.605 4.570 26.835 5.290 ;
        RECT 29.005 4.570 29.235 5.290 ;
        RECT 21.750 5.290 22.090 5.520 ;
        RECT 24.150 5.290 24.490 5.520 ;
        RECT 26.550 5.290 26.890 5.520 ;
        RECT 28.950 5.290 29.290 5.520 ;
    END
  END zn
  OBS
    LAYER Metal1 ;
      RECT 0.805 4.340 19.635 4.570 ;
      RECT 0.805 4.570 1.035 5.290 ;
      RECT 2.605 4.570 2.835 5.290 ;
      RECT 5.005 4.570 5.235 5.290 ;
      RECT 7.405 4.570 7.635 5.290 ;
      RECT 9.805 4.570 10.035 5.290 ;
      RECT 12.205 4.570 12.435 5.290 ;
      RECT 14.605 4.570 14.835 5.290 ;
      RECT 17.005 4.570 17.235 5.290 ;
      RECT 19.405 4.570 19.635 5.290 ;
      RECT 0.150 5.290 1.035 5.520 ;
      RECT 2.550 5.290 2.890 5.520 ;
      RECT 4.950 5.290 5.290 5.520 ;
      RECT 7.350 5.290 7.690 5.520 ;
      RECT 9.750 5.290 10.090 5.520 ;
      RECT 12.150 5.290 12.490 5.520 ;
      RECT 14.550 5.290 14.890 5.520 ;
      RECT 16.950 5.290 17.290 5.520 ;
      RECT 19.350 5.290 19.690 5.520 ;
      RECT 10.950 6.330 11.835 6.560 ;
      RECT 12.805 6.330 14.235 6.560 ;
      RECT 15.205 6.330 16.635 6.560 ;
      RECT 17.605 6.330 19.035 6.560 ;
      RECT 20.005 6.330 21.435 6.560 ;
      RECT 22.405 6.330 23.835 6.560 ;
      RECT 24.805 6.330 26.235 6.560 ;
      RECT 27.205 6.330 28.635 6.560 ;
      RECT 29.605 6.330 30.490 6.560 ;
      RECT 11.605 6.560 11.835 7.150 ;
      RECT 12.805 6.560 13.035 7.150 ;
      RECT 14.005 6.560 14.235 7.150 ;
      RECT 15.205 6.560 15.435 7.150 ;
      RECT 16.405 6.560 16.635 7.150 ;
      RECT 17.605 6.560 17.835 7.150 ;
      RECT 18.805 6.560 19.035 7.150 ;
      RECT 20.005 6.560 20.235 7.150 ;
      RECT 21.205 6.560 21.435 7.150 ;
      RECT 22.405 6.560 22.635 7.150 ;
      RECT 23.605 6.560 23.835 7.150 ;
      RECT 24.805 6.560 25.035 7.150 ;
      RECT 26.005 6.560 26.235 7.150 ;
      RECT 27.205 6.560 27.435 7.150 ;
      RECT 28.405 6.560 28.635 7.150 ;
      RECT 29.605 6.560 29.835 7.150 ;
      RECT 11.605 7.150 13.035 7.380 ;
      RECT 14.005 7.150 15.435 7.380 ;
      RECT 16.405 7.150 17.835 7.380 ;
      RECT 18.805 7.150 20.235 7.380 ;
      RECT 21.205 7.150 22.635 7.380 ;
      RECT 23.605 7.150 25.035 7.380 ;
      RECT 26.005 7.150 27.435 7.380 ;
      RECT 28.405 7.150 29.835 7.380 ;
  END
END gf180mcuf_NR3D4

MACRO gf180mcuf_AN2D1
  CLASS CORE ;
  FOREIGN gf180mcuf_AN2D1 ;
  ORIGIN 0.000 0.000 ;
  SIZE 4.480 BY 7.840 ;
  SYMMETRY X Y R90 ;
  SITE obssite ;
  PIN a1
    DIRECTION INPUT ;
    USE SIGNAL ;
    ANTENNAGATEAREA 0.595000 ;
    PORT
      LAYER Poly2 ;
        RECT 3.180 0.995 3.460 3.075 ;
        RECT 3.140 3.075 3.500 3.435 ;
        RECT 3.180 3.435 3.460 6.845 ;
      LAYER Metal1 ;
        RECT 3.150 3.140 3.490 3.370 ;
        RECT 3.205 3.370 3.435 3.970 ;
    END
  END a1
  PIN a2
    DIRECTION INPUT ;
    USE SIGNAL ;
    ANTENNAGATEAREA 0.595000 ;
    PORT
      LAYER Poly2 ;
        RECT 1.980 0.995 2.260 3.075 ;
        RECT 1.940 3.075 2.300 3.435 ;
        RECT 1.980 3.435 2.260 6.845 ;
      LAYER Metal1 ;
        RECT 1.950 3.140 2.290 3.370 ;
        RECT 2.005 3.370 2.235 3.970 ;
    END
  END a2
  PIN vdd
    DIRECTION INOUT ;
    USE POWER ;
    SHAPE ABUTMENT ;
    PORT
      LAYER Metal1 ;
        RECT 1.350 6.330 1.690 6.560 ;
        RECT 3.750 6.330 4.090 6.560 ;
        RECT 1.405 6.560 1.635 7.610 ;
        RECT 3.805 6.560 4.035 7.610 ;
        RECT 0.000 7.610 4.480 8.070 ;
    END
  END vdd
  PIN vss
    DIRECTION INOUT ;
    USE GROUND ;
    SHAPE ABUTMENT ;
    PORT
      LAYER Metal1 ;
        RECT 0.000 -0.230 4.480 0.230 ;
        RECT 1.405 0.230 1.635 1.280 ;
        RECT 1.350 1.280 1.690 1.510 ;
    END
  END vss
  PIN z
    DIRECTION OUTPUT ;
    USE SIGNAL ;
    ANTENNADIFFAREA 1.408000 ;
    PORT
      LAYER Metal1 ;
        RECT 0.150 1.280 0.490 1.510 ;
        RECT 0.205 1.510 0.435 5.290 ;
        RECT 0.150 5.290 0.490 5.520 ;
    END
  END z
  OBS
    LAYER Metal1 ;
      RECT 3.205 1.280 4.090 1.510 ;
      RECT 3.205 1.510 3.435 2.540 ;
      RECT 0.750 2.540 3.435 2.770 ;
      RECT 2.605 2.770 2.835 5.290 ;
      RECT 2.550 5.290 2.890 5.520 ;
  END
END gf180mcuf_AN2D1

MACRO gf180mcuf_AN2D4
  CLASS CORE ;
  FOREIGN gf180mcuf_AN2D4 ;
  ORIGIN 0.000 0.000 ;
  SIZE 10.640 BY 7.840 ;
  SYMMETRY X Y R90 ;
  SITE obssite ;
  PIN a1
    DIRECTION INPUT ;
    USE SIGNAL ;
    ANTENNAGATEAREA 1.232000 ;
    PORT
      LAYER Poly2 ;
        RECT 6.780 0.995 7.060 2.515 ;
        RECT 7.980 0.995 8.260 2.515 ;
        RECT 6.780 2.515 8.260 2.795 ;
        RECT 7.980 2.795 8.260 3.075 ;
        RECT 7.940 3.075 8.300 3.435 ;
        RECT 7.980 3.435 8.260 4.315 ;
        RECT 6.780 4.315 8.260 4.595 ;
        RECT 6.780 4.595 7.060 6.845 ;
        RECT 7.980 4.595 8.260 6.845 ;
      LAYER Metal1 ;
        RECT 7.950 3.140 8.290 3.370 ;
        RECT 8.005 3.370 8.235 3.970 ;
    END
  END a1
  PIN a2
    DIRECTION INPUT ;
    USE SIGNAL ;
    ANTENNAGATEAREA 1.232000 ;
    PORT
      LAYER Poly2 ;
        RECT 5.580 0.995 5.860 2.475 ;
        RECT 9.180 0.995 9.460 2.515 ;
        RECT 5.540 2.475 5.900 2.835 ;
        RECT 8.540 2.475 8.900 2.515 ;
        RECT 8.540 2.515 9.460 2.795 ;
        RECT 8.540 2.795 8.900 2.835 ;
        RECT 9.180 2.795 9.460 6.845 ;
        RECT 5.580 2.835 5.860 6.845 ;
      LAYER Metal1 ;
        RECT 5.550 2.540 8.890 2.770 ;
    END
  END a2
  PIN vdd
    DIRECTION INOUT ;
    USE POWER ;
    SHAPE ABUTMENT ;
    PORT
      LAYER Metal1 ;
        RECT 0.150 6.330 0.490 6.560 ;
        RECT 2.550 6.330 2.890 6.560 ;
        RECT 4.950 6.330 5.290 6.560 ;
        RECT 7.350 6.330 7.690 6.560 ;
        RECT 9.750 6.330 10.090 6.560 ;
        RECT 0.205 6.560 0.435 7.610 ;
        RECT 2.605 6.560 2.835 7.610 ;
        RECT 5.005 6.560 5.235 7.610 ;
        RECT 7.405 6.560 7.635 7.610 ;
        RECT 9.805 6.560 10.035 7.610 ;
        RECT 0.000 7.610 10.640 8.070 ;
    END
  END vdd
  PIN vss
    DIRECTION INOUT ;
    USE GROUND ;
    SHAPE ABUTMENT ;
    PORT
      LAYER Metal1 ;
        RECT 0.000 -0.230 10.640 0.230 ;
        RECT 0.205 0.230 0.435 1.280 ;
        RECT 2.605 0.230 2.835 1.280 ;
        RECT 5.005 0.230 5.235 1.280 ;
        RECT 9.805 0.230 10.035 1.280 ;
        RECT 0.150 1.280 0.490 1.510 ;
        RECT 2.550 1.280 2.890 1.510 ;
        RECT 4.950 1.280 5.290 1.510 ;
        RECT 9.750 1.280 10.090 1.510 ;
    END
  END vss
  PIN z
    DIRECTION OUTPUT ;
    USE SIGNAL ;
    ANTENNADIFFAREA 4.048000 ;
    PORT
      LAYER Metal1 ;
        RECT 1.350 1.280 2.235 1.510 ;
        RECT 3.750 1.280 4.090 1.510 ;
        RECT 1.405 1.510 1.635 5.290 ;
        RECT 2.005 1.510 2.235 2.540 ;
        RECT 3.805 1.510 4.035 2.540 ;
        RECT 2.005 2.540 4.035 2.770 ;
        RECT 3.805 2.770 4.035 5.290 ;
        RECT 1.350 5.290 1.690 5.520 ;
        RECT 3.750 5.290 4.090 5.520 ;
    END
  END z
  OBS
    LAYER Metal1 ;
      RECT 5.550 0.460 7.035 0.690 ;
      RECT 6.805 0.690 7.035 1.280 ;
      RECT 6.805 1.280 7.690 1.510 ;
      RECT 4.950 4.340 8.835 4.570 ;
      RECT 6.205 4.570 6.435 5.290 ;
      RECT 8.605 4.570 8.835 5.290 ;
      RECT 6.150 5.290 6.490 5.520 ;
      RECT 8.550 5.290 8.890 5.520 ;
  END
END gf180mcuf_AN2D4

MACRO gf180mcuf_OR2D1
  CLASS CORE ;
  FOREIGN gf180mcuf_OR2D1 ;
  ORIGIN 0.000 0.000 ;
  SIZE 4.480 BY 7.840 ;
  SYMMETRY X Y R90 ;
  SITE obssite ;
  PIN a1
    DIRECTION INPUT ;
    USE SIGNAL ;
    ANTENNAGATEAREA 0.595000 ;
    PORT
      LAYER Poly2 ;
        RECT 3.180 0.995 3.460 2.475 ;
        RECT 3.140 2.475 3.500 2.835 ;
        RECT 3.180 2.835 3.460 6.845 ;
      LAYER Metal1 ;
        RECT 3.150 2.540 3.490 2.770 ;
        RECT 3.205 2.770 3.435 3.370 ;
    END
  END a1
  PIN a2
    DIRECTION INPUT ;
    USE SIGNAL ;
    ANTENNAGATEAREA 0.595000 ;
    PORT
      LAYER Poly2 ;
        RECT 1.980 0.995 2.260 3.075 ;
        RECT 1.940 3.075 2.300 3.435 ;
        RECT 1.980 3.435 2.260 6.845 ;
      LAYER Metal1 ;
        RECT 1.950 3.140 2.290 3.370 ;
        RECT 2.005 3.370 2.235 3.970 ;
    END
  END a2
  PIN vdd
    DIRECTION INOUT ;
    USE POWER ;
    SHAPE ABUTMENT ;
    PORT
      LAYER Metal1 ;
        RECT 1.350 6.330 1.690 6.560 ;
        RECT 1.405 6.560 1.635 7.610 ;
        RECT 0.000 7.610 4.480 8.070 ;
    END
  END vdd
  PIN vss
    DIRECTION INOUT ;
    USE GROUND ;
    SHAPE ABUTMENT ;
    PORT
      LAYER Metal1 ;
        RECT 0.000 -0.230 4.480 0.230 ;
        RECT 1.405 0.230 1.635 1.280 ;
        RECT 3.805 0.230 4.035 1.280 ;
        RECT 1.350 1.280 1.690 1.510 ;
        RECT 3.750 1.280 4.090 1.510 ;
    END
  END vss
  PIN z
    DIRECTION OUTPUT ;
    USE SIGNAL ;
    ANTENNADIFFAREA 1.360000 ;
    PORT
      LAYER Metal1 ;
        RECT 0.150 1.280 0.490 1.510 ;
        RECT 0.205 1.510 0.435 5.290 ;
        RECT 0.150 5.290 0.490 5.520 ;
    END
  END z
  OBS
    LAYER Metal1 ;
      RECT 2.550 1.280 2.890 1.510 ;
      RECT 2.605 1.510 2.835 2.540 ;
      RECT 1.350 2.540 2.835 2.770 ;
      RECT 2.605 2.770 2.835 4.340 ;
      RECT 2.605 4.340 4.035 4.570 ;
      RECT 3.805 4.570 4.035 5.290 ;
      RECT 3.750 5.290 4.090 5.520 ;
  END
END gf180mcuf_OR2D1

MACRO gf180mcuf_AO21D1
  CLASS CORE ;
  FOREIGN gf180mcuf_AO21D1 ;
  ORIGIN 0.000 0.000 ;
  SIZE 5.600 BY 7.840 ;
  SYMMETRY X Y R90 ;
  SITE obssite ;
  PIN a1
    DIRECTION INPUT ;
    USE SIGNAL ;
    ANTENNAGATEAREA 0.616000 ;
    PORT
      LAYER Poly2 ;
        RECT 1.980 0.995 2.260 2.475 ;
        RECT 1.940 2.475 2.300 2.835 ;
        RECT 1.980 2.835 2.260 6.845 ;
      LAYER Metal1 ;
        RECT 1.950 2.540 2.290 2.770 ;
        RECT 2.005 2.770 2.235 3.370 ;
    END
  END a1
  PIN a2
    DIRECTION INPUT ;
    USE SIGNAL ;
    ANTENNAGATEAREA 0.616000 ;
    PORT
      LAYER Poly2 ;
        RECT 0.780 0.995 1.060 2.475 ;
        RECT 0.740 2.475 1.100 2.835 ;
        RECT 0.780 2.835 1.060 6.845 ;
      LAYER Metal1 ;
        RECT 0.750 2.540 1.090 2.770 ;
        RECT 0.805 2.770 1.035 3.370 ;
    END
  END a2
  PIN b
    DIRECTION INPUT ;
    USE SIGNAL ;
    ANTENNAGATEAREA 0.616000 ;
    PORT
      LAYER Poly2 ;
        RECT 3.180 0.995 3.460 3.075 ;
        RECT 3.140 3.075 3.500 3.435 ;
        RECT 3.180 3.435 3.460 6.845 ;
      LAYER Metal1 ;
        RECT 3.150 3.140 3.490 3.370 ;
        RECT 3.205 3.370 3.435 3.970 ;
    END
  END b
  PIN vdd
    DIRECTION INOUT ;
    USE POWER ;
    SHAPE ABUTMENT ;
    PORT
      LAYER Metal1 ;
        RECT 3.750 6.330 4.090 6.560 ;
        RECT 3.805 6.560 4.035 7.610 ;
        RECT 0.000 7.610 5.600 8.070 ;
    END
  END vdd
  PIN vss
    DIRECTION INOUT ;
    USE GROUND ;
    SHAPE ABUTMENT ;
    PORT
      LAYER Metal1 ;
        RECT 0.000 -0.230 5.600 0.230 ;
        RECT 0.205 0.230 0.435 1.280 ;
        RECT 3.805 0.230 4.035 1.280 ;
        RECT 0.150 1.280 0.490 1.510 ;
        RECT 3.750 1.280 4.090 1.510 ;
    END
  END vss
  PIN z
    DIRECTION OUTPUT ;
    USE SIGNAL ;
    ANTENNADIFFAREA 1.408000 ;
    PORT
      LAYER Metal1 ;
        RECT 4.950 1.280 5.290 1.510 ;
        RECT 5.005 1.510 5.235 5.290 ;
        RECT 4.950 5.290 5.290 5.520 ;
    END
  END z
  OBS
    LAYER Metal1 ;
      RECT 2.550 1.280 2.890 1.510 ;
      RECT 2.605 1.510 2.835 2.540 ;
      RECT 2.605 2.540 4.690 2.770 ;
      RECT 2.605 2.770 2.835 4.340 ;
      RECT 1.405 4.340 2.835 4.570 ;
      RECT 1.405 4.570 1.635 5.290 ;
      RECT 1.350 5.290 1.690 5.520 ;
      RECT 0.150 6.330 1.035 6.560 ;
      RECT 2.005 6.330 2.890 6.560 ;
      RECT 0.805 6.560 1.035 7.150 ;
      RECT 2.005 6.560 2.235 7.150 ;
      RECT 0.805 7.150 2.235 7.380 ;
  END
END gf180mcuf_AO21D1

MACRO gf180mcuf_OA21D1
  CLASS CORE ;
  FOREIGN gf180mcuf_OA21D1 ;
  ORIGIN 0.000 0.000 ;
  SIZE 5.600 BY 7.840 ;
  SYMMETRY X Y R90 ;
  SITE obssite ;
  PIN a1
    DIRECTION INPUT ;
    USE SIGNAL ;
    ANTENNAGATEAREA 0.616000 ;
    PORT
      LAYER Poly2 ;
        RECT 3.180 0.995 3.460 3.075 ;
        RECT 3.140 3.075 3.500 3.435 ;
        RECT 3.180 3.435 3.460 6.845 ;
      LAYER Metal1 ;
        RECT 3.150 3.140 3.490 3.370 ;
        RECT 3.205 3.370 3.435 3.970 ;
    END
  END a1
  PIN a2
    DIRECTION INPUT ;
    USE SIGNAL ;
    ANTENNAGATEAREA 0.616000 ;
    PORT
      LAYER Poly2 ;
        RECT 4.380 0.995 4.660 2.475 ;
        RECT 4.340 2.475 4.700 2.835 ;
        RECT 4.380 2.835 4.660 6.845 ;
      LAYER Metal1 ;
        RECT 4.350 2.540 4.690 2.770 ;
        RECT 4.405 2.770 4.635 3.370 ;
    END
  END a2
  PIN b
    DIRECTION INPUT ;
    USE SIGNAL ;
    ANTENNAGATEAREA 0.616000 ;
    PORT
      LAYER Poly2 ;
        RECT 1.980 0.995 2.260 3.075 ;
        RECT 1.940 3.075 2.300 3.435 ;
        RECT 1.980 3.435 2.260 6.845 ;
      LAYER Metal1 ;
        RECT 1.950 3.140 2.290 3.370 ;
        RECT 2.005 3.370 2.235 3.970 ;
    END
  END b
  PIN vdd
    DIRECTION INOUT ;
    USE POWER ;
    SHAPE ABUTMENT ;
    PORT
      LAYER Metal1 ;
        RECT 1.350 6.330 1.690 6.560 ;
        RECT 4.950 6.330 5.290 6.560 ;
        RECT 1.405 6.560 1.635 7.610 ;
        RECT 5.005 6.560 5.235 7.610 ;
        RECT 0.000 7.610 5.600 8.070 ;
    END
  END vdd
  PIN vss
    DIRECTION INOUT ;
    USE GROUND ;
    SHAPE ABUTMENT ;
    PORT
      LAYER Metal1 ;
        RECT 0.000 -0.230 5.600 0.230 ;
        RECT 1.405 0.230 1.635 1.280 ;
        RECT 1.350 1.280 1.690 1.510 ;
    END
  END vss
  PIN z
    DIRECTION OUTPUT ;
    USE SIGNAL ;
    ANTENNADIFFAREA 1.408000 ;
    PORT
      LAYER Metal1 ;
        RECT 0.150 1.280 0.490 1.510 ;
        RECT 0.205 1.510 0.435 5.290 ;
        RECT 0.150 5.290 0.490 5.520 ;
    END
  END z
  OBS
    LAYER Metal1 ;
      RECT 2.605 0.460 4.635 0.690 ;
      RECT 2.605 0.690 2.835 1.280 ;
      RECT 4.405 0.690 4.635 1.280 ;
      RECT 2.550 1.280 2.890 1.510 ;
      RECT 3.205 1.280 4.090 1.510 ;
      RECT 4.405 1.280 5.290 1.510 ;
      RECT 3.205 1.510 3.435 2.540 ;
      RECT 0.750 2.540 3.435 2.770 ;
      RECT 2.605 2.770 2.835 5.290 ;
      RECT 2.550 5.290 2.890 5.520 ;
  END
END gf180mcuf_OA21D1

MACRO gf180mcuf_AOI21D1
  CLASS CORE ;
  FOREIGN gf180mcuf_AOI21D1 ;
  ORIGIN 0.000 0.000 ;
  SIZE 4.480 BY 7.840 ;
  SYMMETRY X Y R90 ;
  SITE obssite ;
  PIN a1
    DIRECTION INPUT ;
    USE SIGNAL ;
    ANTENNAGATEAREA 0.616000 ;
    PORT
      LAYER Poly2 ;
        RECT 1.980 0.995 2.260 2.475 ;
        RECT 1.940 2.475 2.300 2.835 ;
        RECT 1.980 2.835 2.260 6.845 ;
      LAYER Metal1 ;
        RECT 1.950 2.540 2.290 2.770 ;
        RECT 2.005 2.770 2.235 3.370 ;
    END
  END a1
  PIN a2
    DIRECTION INPUT ;
    USE SIGNAL ;
    ANTENNAGATEAREA 0.616000 ;
    PORT
      LAYER Poly2 ;
        RECT 3.180 0.995 3.460 2.475 ;
        RECT 3.140 2.475 3.500 2.835 ;
        RECT 3.180 2.835 3.460 6.845 ;
      LAYER Metal1 ;
        RECT 3.150 2.540 3.490 2.770 ;
        RECT 3.205 2.770 3.435 3.370 ;
    END
  END a2
  PIN b
    DIRECTION INPUT ;
    USE SIGNAL ;
    ANTENNAGATEAREA 0.616000 ;
    PORT
      LAYER Poly2 ;
        RECT 0.780 0.995 1.060 2.475 ;
        RECT 0.740 2.475 1.100 2.835 ;
        RECT 0.780 2.835 1.060 6.845 ;
      LAYER Metal1 ;
        RECT 0.750 2.540 1.090 2.770 ;
        RECT 0.805 2.770 1.035 3.370 ;
    END
  END b
  PIN vdd
    DIRECTION INOUT ;
    USE POWER ;
    SHAPE ABUTMENT ;
    PORT
      LAYER Metal1 ;
        RECT 0.150 6.330 0.490 6.560 ;
        RECT 0.205 6.560 0.435 7.610 ;
        RECT 0.000 7.610 4.480 8.070 ;
    END
  END vdd
  PIN vss
    DIRECTION INOUT ;
    USE GROUND ;
    SHAPE ABUTMENT ;
    PORT
      LAYER Metal1 ;
        RECT 0.000 -0.230 4.480 0.230 ;
        RECT 0.205 0.230 0.435 1.280 ;
        RECT 3.805 0.230 4.035 1.280 ;
        RECT 0.150 1.280 0.490 1.510 ;
        RECT 3.750 1.280 4.090 1.510 ;
    END
  END vss
  PIN zn
    DIRECTION OUTPUT ;
    USE SIGNAL ;
    ANTENNADIFFAREA 2.024000 ;
    PORT
      LAYER Metal1 ;
        RECT 1.350 1.280 1.690 1.510 ;
        RECT 1.405 1.510 1.635 4.340 ;
        RECT 1.405 4.340 2.835 4.570 ;
        RECT 2.605 4.570 2.835 5.290 ;
        RECT 2.550 5.290 2.890 5.520 ;
    END
  END zn
  OBS
    LAYER Metal1 ;
      RECT 1.350 6.330 2.235 6.560 ;
      RECT 3.205 6.330 4.090 6.560 ;
      RECT 2.005 6.560 2.235 7.150 ;
      RECT 3.205 6.560 3.435 7.150 ;
      RECT 2.005 7.150 3.435 7.380 ;
  END
END gf180mcuf_AOI21D1

MACRO gf180mcuf_OAI21D1
  CLASS CORE ;
  FOREIGN gf180mcuf_OAI21D1 ;
  ORIGIN 0.000 0.000 ;
  SIZE 4.480 BY 7.840 ;
  SYMMETRY X Y R90 ;
  SITE obssite ;
  PIN a1
    DIRECTION INPUT ;
    USE SIGNAL ;
    ANTENNAGATEAREA 0.616000 ;
    PORT
      LAYER Poly2 ;
        RECT 1.980 0.995 2.260 2.475 ;
        RECT 1.940 2.475 2.300 2.835 ;
        RECT 1.980 2.835 2.260 6.845 ;
      LAYER Metal1 ;
        RECT 1.950 2.540 2.290 2.770 ;
        RECT 2.005 2.770 2.235 3.370 ;
    END
  END a1
  PIN a2
    DIRECTION INPUT ;
    USE SIGNAL ;
    ANTENNAGATEAREA 0.616000 ;
    PORT
      LAYER Poly2 ;
        RECT 0.780 0.995 1.060 2.475 ;
        RECT 0.740 2.475 1.100 2.835 ;
        RECT 0.780 2.835 1.060 6.845 ;
      LAYER Metal1 ;
        RECT 0.750 2.540 1.090 2.770 ;
        RECT 0.805 2.770 1.035 3.370 ;
    END
  END a2
  PIN b
    DIRECTION INPUT ;
    USE SIGNAL ;
    ANTENNAGATEAREA 0.616000 ;
    PORT
      LAYER Poly2 ;
        RECT 3.180 0.995 3.460 2.475 ;
        RECT 3.140 2.475 3.500 2.835 ;
        RECT 3.180 2.835 3.460 6.845 ;
      LAYER Metal1 ;
        RECT 3.150 2.540 3.490 2.770 ;
        RECT 3.205 2.770 3.435 3.370 ;
    END
  END b
  PIN vdd
    DIRECTION INOUT ;
    USE POWER ;
    SHAPE ABUTMENT ;
    PORT
      LAYER Metal1 ;
        RECT 0.150 6.330 0.490 6.560 ;
        RECT 3.750 6.330 4.090 6.560 ;
        RECT 0.205 6.560 0.435 7.610 ;
        RECT 3.805 6.560 4.035 7.610 ;
        RECT 0.000 7.610 4.480 8.070 ;
    END
  END vdd
  PIN vss
    DIRECTION INOUT ;
    USE GROUND ;
    SHAPE ABUTMENT ;
    PORT
      LAYER Metal1 ;
        RECT 0.000 -0.230 4.480 0.230 ;
        RECT 3.805 0.230 4.035 1.280 ;
        RECT 3.750 1.280 4.090 1.510 ;
    END
  END vss
  PIN zn
    DIRECTION OUTPUT ;
    USE SIGNAL ;
    ANTENNADIFFAREA 2.024000 ;
    PORT
      LAYER Metal1 ;
        RECT 1.350 1.280 1.690 1.510 ;
        RECT 1.405 1.510 1.635 4.340 ;
        RECT 1.405 4.340 2.835 4.570 ;
        RECT 2.605 4.570 2.835 5.290 ;
        RECT 2.550 5.290 2.890 5.520 ;
    END
  END zn
  OBS
    LAYER Metal1 ;
      RECT 0.805 0.460 2.235 0.690 ;
      RECT 0.805 0.690 1.035 1.280 ;
      RECT 2.005 0.690 2.235 1.280 ;
      RECT 0.150 1.280 1.035 1.510 ;
      RECT 2.005 1.280 2.890 1.510 ;
  END
END gf180mcuf_OAI21D1

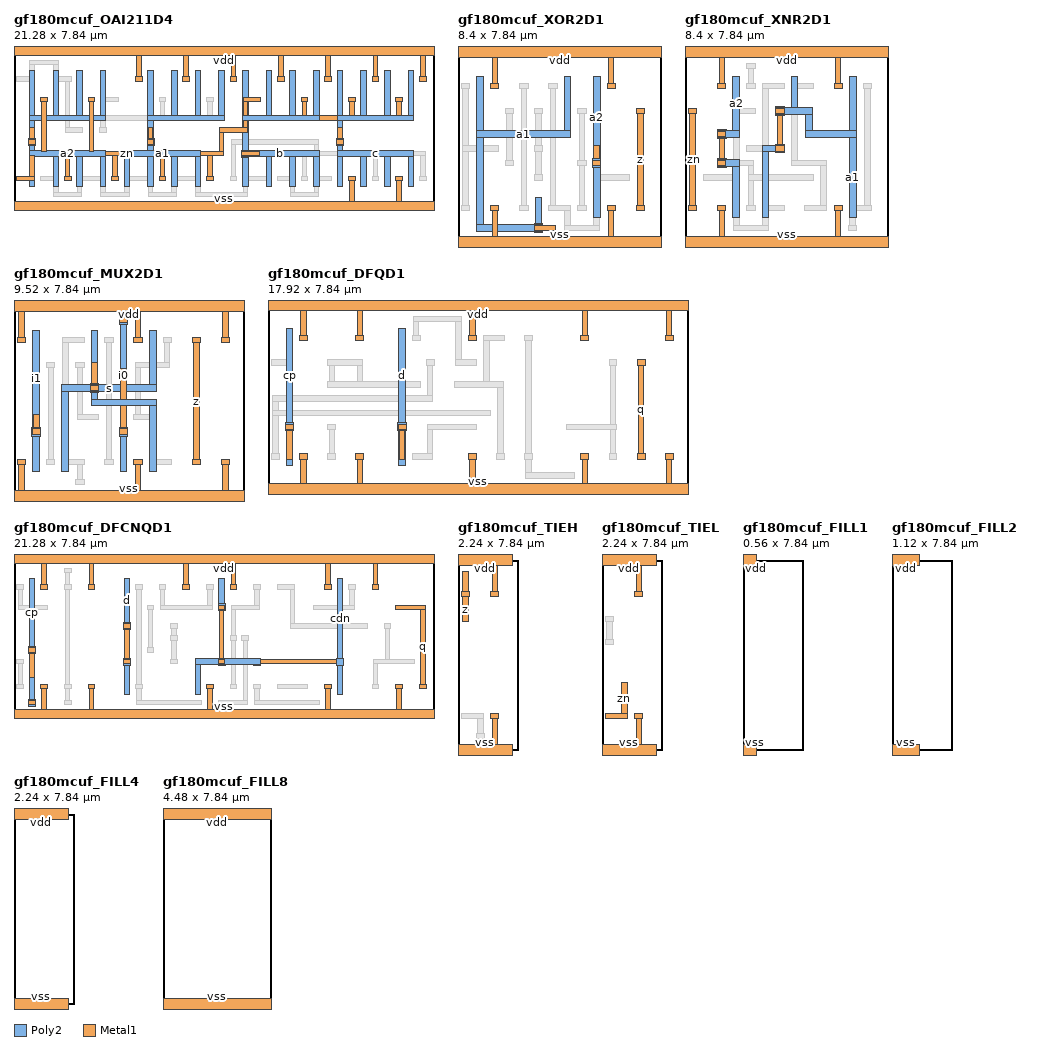
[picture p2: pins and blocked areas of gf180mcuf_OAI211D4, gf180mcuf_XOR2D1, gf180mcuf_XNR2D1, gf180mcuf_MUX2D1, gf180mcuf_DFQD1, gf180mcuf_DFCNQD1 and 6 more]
MACRO gf180mcuf_OAI211D4
  CLASS CORE ;
  FOREIGN gf180mcuf_OAI211D4 ;
  ORIGIN 0.000 0.000 ;
  SIZE 21.280 BY 7.840 ;
  SYMMETRY X Y R90 ;
  SITE obssite ;
  PIN a1
    DIRECTION INPUT ;
    USE SIGNAL ;
    ANTENNAGATEAREA 2.464000 ;
    PORT
      LAYER Poly2 ;
        RECT 5.580 0.995 5.860 2.515 ;
        RECT 6.780 0.995 7.060 2.515 ;
        RECT 7.980 0.995 8.260 2.515 ;
        RECT 9.180 0.995 9.460 2.515 ;
        RECT 5.580 2.515 9.460 2.795 ;
        RECT 6.780 2.795 7.060 3.075 ;
        RECT 6.740 3.075 7.100 3.435 ;
        RECT 6.780 3.435 7.060 4.315 ;
        RECT 6.780 4.315 10.660 4.595 ;
        RECT 6.780 4.595 7.060 6.845 ;
        RECT 7.980 4.595 8.260 6.845 ;
        RECT 9.180 4.595 9.460 6.845 ;
        RECT 10.380 4.595 10.660 6.845 ;
      LAYER Metal1 ;
        RECT 6.750 3.140 7.090 3.370 ;
        RECT 6.805 3.370 7.035 3.970 ;
    END
  END a1
  PIN a2
    DIRECTION INPUT ;
    USE SIGNAL ;
    ANTENNAGATEAREA 2.464000 ;
    PORT
      LAYER Poly2 ;
        RECT 0.780 0.995 1.060 2.515 ;
        RECT 1.980 0.995 2.260 2.515 ;
        RECT 3.180 0.995 3.460 2.515 ;
        RECT 4.380 0.995 4.660 2.515 ;
        RECT 0.780 2.515 4.660 2.795 ;
        RECT 0.780 2.795 1.060 3.075 ;
        RECT 0.740 3.075 1.100 3.435 ;
        RECT 0.780 3.435 1.060 4.315 ;
        RECT 0.780 4.315 4.660 4.595 ;
        RECT 0.780 4.595 1.060 6.845 ;
        RECT 1.980 4.595 2.260 6.845 ;
        RECT 3.180 4.595 3.460 6.845 ;
        RECT 4.380 4.595 4.660 6.845 ;
      LAYER Metal1 ;
        RECT 0.750 3.140 1.090 3.370 ;
        RECT 0.805 3.370 1.035 3.970 ;
    END
  END a2
  PIN b
    DIRECTION INPUT ;
    USE SIGNAL ;
    ANTENNAGATEAREA 2.464000 ;
    PORT
      LAYER Poly2 ;
        RECT 11.580 0.995 11.860 2.475 ;
        RECT 12.780 0.995 13.060 2.515 ;
        RECT 13.980 0.995 14.260 2.515 ;
        RECT 15.180 0.995 15.460 2.515 ;
        RECT 11.540 2.475 11.900 2.515 ;
        RECT 11.540 2.515 15.460 2.795 ;
        RECT 11.540 2.795 11.900 2.835 ;
        RECT 11.580 2.835 11.860 4.315 ;
        RECT 11.580 4.315 15.460 4.595 ;
        RECT 11.580 4.595 11.860 6.845 ;
        RECT 12.780 4.595 13.060 6.845 ;
        RECT 13.980 4.595 14.260 6.845 ;
        RECT 15.180 4.595 15.460 6.845 ;
      LAYER Metal1 ;
        RECT 11.550 2.540 12.435 2.770 ;
    END
  END b
  PIN c
    DIRECTION INPUT ;
    USE SIGNAL ;
    ANTENNAGATEAREA 2.464000 ;
    PORT
      LAYER Poly2 ;
        RECT 16.380 0.995 16.660 2.515 ;
        RECT 17.580 0.995 17.860 2.515 ;
        RECT 18.780 0.995 19.060 2.515 ;
        RECT 19.980 0.995 20.260 2.515 ;
        RECT 16.380 2.515 20.260 2.795 ;
        RECT 16.380 2.795 16.660 3.075 ;
        RECT 16.340 3.075 16.700 3.435 ;
        RECT 16.380 3.435 16.660 4.315 ;
        RECT 16.380 4.315 20.260 4.595 ;
        RECT 16.380 4.595 16.660 6.845 ;
        RECT 17.580 4.595 17.860 6.845 ;
        RECT 18.780 4.595 19.060 6.845 ;
        RECT 19.980 4.595 20.260 6.845 ;
      LAYER Metal1 ;
        RECT 16.350 3.140 16.690 3.370 ;
        RECT 16.405 3.370 16.635 3.970 ;
    END
  END c
  PIN vdd
    DIRECTION INOUT ;
    USE POWER ;
    SHAPE ABUTMENT ;
    PORT
      LAYER Metal1 ;
        RECT 6.150 6.330 6.490 6.560 ;
        RECT 8.550 6.330 8.890 6.560 ;
        RECT 10.950 6.330 11.290 6.560 ;
        RECT 13.350 6.330 13.690 6.560 ;
        RECT 15.750 6.330 16.090 6.560 ;
        RECT 18.150 6.330 18.490 6.560 ;
        RECT 20.550 6.330 20.890 6.560 ;
        RECT 6.205 6.560 6.435 7.610 ;
        RECT 8.605 6.560 8.835 7.610 ;
        RECT 11.005 6.560 11.235 7.610 ;
        RECT 13.405 6.560 13.635 7.610 ;
        RECT 15.805 6.560 16.035 7.610 ;
        RECT 18.205 6.560 18.435 7.610 ;
        RECT 20.605 6.560 20.835 7.610 ;
        RECT 0.000 7.610 21.280 8.070 ;
    END
  END vdd
  PIN vss
    DIRECTION INOUT ;
    USE GROUND ;
    SHAPE ABUTMENT ;
    PORT
      LAYER Metal1 ;
        RECT 0.000 -0.230 21.280 0.230 ;
        RECT 17.005 0.230 17.235 1.280 ;
        RECT 19.405 0.230 19.635 1.280 ;
        RECT 16.950 1.280 17.290 1.510 ;
        RECT 19.350 1.280 19.690 1.510 ;
    END
  END vss
  PIN zn
    DIRECTION OUTPUT ;
    USE SIGNAL ;
    ANTENNADIFFAREA 10.960000 ;
    PORT
      LAYER Metal1 ;
        RECT 0.150 1.280 1.035 1.510 ;
        RECT 2.550 1.280 2.890 1.510 ;
        RECT 4.950 1.280 5.290 1.510 ;
        RECT 7.350 1.280 7.690 1.510 ;
        RECT 9.750 1.280 10.090 1.510 ;
        RECT 0.805 1.510 1.035 2.540 ;
        RECT 2.605 1.510 2.835 2.540 ;
        RECT 5.005 1.510 5.235 2.540 ;
        RECT 7.405 1.510 7.635 2.540 ;
        RECT 9.805 1.510 10.035 2.540 ;
        RECT 0.805 2.540 10.635 2.770 ;
        RECT 1.405 2.770 1.635 5.290 ;
        RECT 3.805 2.770 4.035 5.290 ;
        RECT 10.405 2.770 10.635 3.740 ;
        RECT 10.405 3.740 11.835 3.970 ;
        RECT 11.605 3.970 11.835 4.340 ;
        RECT 11.605 4.340 19.635 4.570 ;
        RECT 11.605 4.570 11.835 5.290 ;
        RECT 14.605 4.570 14.835 5.290 ;
        RECT 17.005 4.570 17.235 5.290 ;
        RECT 19.405 4.570 19.635 5.290 ;
        RECT 1.350 5.290 1.690 5.520 ;
        RECT 3.750 5.290 4.090 5.520 ;
        RECT 11.605 5.290 12.490 5.520 ;
        RECT 14.550 5.290 14.890 5.520 ;
        RECT 16.950 5.290 17.290 5.520 ;
        RECT 19.350 5.290 19.690 5.520 ;
    END
  END zn
  OBS
    LAYER Metal1 ;
      RECT 2.005 0.460 3.435 0.690 ;
      RECT 4.405 0.460 5.835 0.690 ;
      RECT 6.805 0.460 8.235 0.690 ;
      RECT 9.205 0.460 11.835 0.690 ;
      RECT 14.005 0.460 15.435 0.690 ;
      RECT 2.005 0.690 2.235 1.280 ;
      RECT 3.205 0.690 3.435 1.280 ;
      RECT 4.405 0.690 4.635 1.280 ;
      RECT 5.605 0.690 5.835 1.280 ;
      RECT 6.805 0.690 7.035 1.280 ;
      RECT 8.005 0.690 8.235 1.280 ;
      RECT 9.205 0.690 9.435 1.280 ;
      RECT 11.605 0.690 11.835 1.280 ;
      RECT 14.005 0.690 14.235 1.280 ;
      RECT 15.205 0.690 15.435 1.280 ;
      RECT 1.350 1.280 2.235 1.510 ;
      RECT 3.205 1.280 4.635 1.510 ;
      RECT 5.605 1.280 7.035 1.510 ;
      RECT 8.005 1.280 9.435 1.510 ;
      RECT 10.950 1.280 11.290 1.510 ;
      RECT 11.605 1.280 13.035 1.510 ;
      RECT 13.350 1.280 14.235 1.510 ;
      RECT 14.550 1.280 14.890 1.510 ;
      RECT 15.205 1.280 16.090 1.510 ;
      RECT 18.150 1.280 18.490 1.510 ;
      RECT 20.550 1.280 20.890 1.510 ;
      RECT 11.005 1.510 11.235 3.140 ;
      RECT 12.805 1.510 13.035 2.540 ;
      RECT 14.605 1.510 14.835 2.540 ;
      RECT 15.205 1.510 15.435 2.540 ;
      RECT 18.205 1.510 18.435 2.540 ;
      RECT 20.605 1.510 20.835 2.540 ;
      RECT 12.805 2.540 14.835 2.770 ;
      RECT 15.205 2.540 20.835 2.770 ;
      RECT 15.205 2.770 15.435 3.140 ;
      RECT 11.005 3.140 15.435 3.370 ;
      RECT 2.605 3.740 3.490 3.970 ;
      RECT 4.350 3.740 4.690 3.970 ;
      RECT 2.605 3.970 2.835 6.330 ;
      RECT 4.405 3.970 4.635 4.340 ;
      RECT 4.405 4.340 10.035 4.570 ;
      RECT 4.405 4.570 4.635 5.290 ;
      RECT 7.405 4.570 7.635 5.290 ;
      RECT 9.805 4.570 10.035 5.290 ;
      RECT 4.405 5.290 5.290 5.520 ;
      RECT 7.350 5.290 7.690 5.520 ;
      RECT 9.750 5.290 10.090 5.520 ;
      RECT 0.150 6.330 1.035 6.560 ;
      RECT 2.005 6.330 2.890 6.560 ;
      RECT 0.805 6.560 1.035 7.150 ;
      RECT 2.005 6.560 2.235 7.150 ;
      RECT 0.805 7.150 2.235 7.380 ;
  END
END gf180mcuf_OAI211D4

MACRO gf180mcuf_XOR2D1
  CLASS CORE ;
  FOREIGN gf180mcuf_XOR2D1 ;
  ORIGIN 0.000 0.000 ;
  SIZE 8.400 BY 7.840 ;
  SYMMETRY X Y R90 ;
  SITE obssite ;
  PIN a1
    DIRECTION INPUT ;
    USE SIGNAL ;
    ANTENNAGATEAREA 0.616000 ;
    PORT
      LAYER Poly2 ;
        RECT 3.140 0.395 3.500 0.435 ;
        RECT 0.780 0.435 3.500 0.715 ;
        RECT 0.780 0.715 1.060 4.315 ;
        RECT 3.140 0.715 3.500 0.755 ;
        RECT 3.180 0.755 3.460 1.835 ;
        RECT 0.780 4.315 4.660 4.595 ;
        RECT 0.780 4.595 1.060 6.845 ;
        RECT 4.380 4.595 4.660 6.845 ;
      LAYER Metal1 ;
        RECT 3.150 0.460 4.035 0.690 ;
    END
  END a1
  PIN a2
    DIRECTION INPUT ;
    USE SIGNAL ;
    ANTENNAGATEAREA 0.616000 ;
    PORT
      LAYER Poly2 ;
        RECT 5.580 0.995 5.860 3.075 ;
        RECT 5.540 3.075 5.900 3.435 ;
        RECT 5.580 3.435 5.860 6.845 ;
      LAYER Metal1 ;
        RECT 5.550 3.140 5.890 3.370 ;
        RECT 5.605 3.370 5.835 3.970 ;
    END
  END a2
  PIN vdd
    DIRECTION INOUT ;
    USE POWER ;
    SHAPE ABUTMENT ;
    PORT
      LAYER Metal1 ;
        RECT 1.350 6.330 1.690 6.560 ;
        RECT 6.150 6.330 6.490 6.560 ;
        RECT 1.405 6.560 1.635 7.610 ;
        RECT 6.205 6.560 6.435 7.610 ;
        RECT 0.000 7.610 8.400 8.070 ;
    END
  END vdd
  PIN vss
    DIRECTION INOUT ;
    USE GROUND ;
    SHAPE ABUTMENT ;
    PORT
      LAYER Metal1 ;
        RECT 0.000 -0.230 8.400 0.230 ;
        RECT 1.405 0.230 1.635 1.280 ;
        RECT 6.205 0.230 6.435 1.280 ;
        RECT 1.350 1.280 1.690 1.510 ;
        RECT 6.150 1.280 6.490 1.510 ;
    END
  END vss
  PIN z
    DIRECTION OUTPUT ;
    USE SIGNAL ;
    ANTENNADIFFAREA 1.408000 ;
    PORT
      LAYER Metal1 ;
        RECT 7.350 1.280 7.690 1.510 ;
        RECT 7.405 1.510 7.635 5.290 ;
        RECT 7.350 5.290 7.690 5.520 ;
    END
  END z
  OBS
    LAYER Metal1 ;
      RECT 4.405 0.460 5.835 0.690 ;
      RECT 4.405 0.690 4.635 1.280 ;
      RECT 5.605 0.690 5.835 2.540 ;
      RECT 0.150 1.280 0.490 1.510 ;
      RECT 2.550 1.280 2.890 1.510 ;
      RECT 3.750 1.280 4.635 1.510 ;
      RECT 4.950 1.280 5.290 1.510 ;
      RECT 0.205 1.510 0.435 3.740 ;
      RECT 2.605 1.510 2.835 6.330 ;
      RECT 3.805 1.510 4.035 6.330 ;
      RECT 5.005 1.510 5.235 3.140 ;
      RECT 3.150 2.540 3.490 2.770 ;
      RECT 5.605 2.540 7.090 2.770 ;
      RECT 3.205 2.770 3.435 3.740 ;
      RECT 1.950 3.140 2.290 3.370 ;
      RECT 4.950 3.140 5.290 3.370 ;
      RECT 2.005 3.370 2.235 5.290 ;
      RECT 5.005 3.370 5.235 5.290 ;
      RECT 0.205 3.740 1.690 3.970 ;
      RECT 3.150 3.740 3.490 3.970 ;
      RECT 0.205 3.970 0.435 6.330 ;
      RECT 3.205 3.970 3.435 5.290 ;
      RECT 1.950 5.290 2.290 5.520 ;
      RECT 3.150 5.290 3.490 5.520 ;
      RECT 4.950 5.290 5.290 5.520 ;
      RECT 0.150 6.330 0.490 6.560 ;
      RECT 2.550 6.330 2.890 6.560 ;
      RECT 3.750 6.330 4.090 6.560 ;
  END
END gf180mcuf_XOR2D1

MACRO gf180mcuf_XNR2D1
  CLASS CORE ;
  FOREIGN gf180mcuf_XNR2D1 ;
  ORIGIN 0.000 0.000 ;
  SIZE 8.400 BY 7.840 ;
  SYMMETRY X Y R90 ;
  SITE obssite ;
  PIN a1
    DIRECTION INPUT ;
    USE SIGNAL ;
    ANTENNAGATEAREA 0.616000 ;
    PORT
      LAYER Poly2 ;
        RECT 3.180 0.995 3.460 3.715 ;
        RECT 6.780 0.995 7.060 4.315 ;
        RECT 3.740 3.675 4.100 3.715 ;
        RECT 3.180 3.715 4.100 3.995 ;
        RECT 3.740 3.995 4.100 4.035 ;
        RECT 4.980 4.315 7.060 4.595 ;
        RECT 4.980 4.595 5.260 5.265 ;
        RECT 6.780 4.595 7.060 6.845 ;
        RECT 3.740 5.225 4.100 5.265 ;
        RECT 3.740 5.265 5.260 5.545 ;
        RECT 3.740 5.545 4.100 5.585 ;
        RECT 4.380 5.545 4.660 6.845 ;
      LAYER Metal1 ;
        RECT 3.750 3.740 4.090 3.970 ;
        RECT 3.805 3.970 4.035 5.290 ;
        RECT 3.750 5.290 4.090 5.520 ;
    END
  END a1
  PIN a2
    DIRECTION INPUT ;
    USE SIGNAL ;
    ANTENNAGATEAREA 0.616000 ;
    PORT
      LAYER Poly2 ;
        RECT 1.980 0.995 2.260 3.115 ;
        RECT 1.340 3.075 1.700 3.115 ;
        RECT 1.340 3.115 2.260 3.395 ;
        RECT 1.340 3.395 1.700 3.435 ;
        RECT 1.340 4.275 1.700 4.315 ;
        RECT 1.340 4.315 2.260 4.595 ;
        RECT 1.340 4.595 1.700 4.635 ;
        RECT 1.980 4.595 2.260 6.845 ;
      LAYER Metal1 ;
        RECT 1.350 3.140 1.690 3.370 ;
        RECT 1.405 3.370 1.635 4.340 ;
        RECT 1.350 4.340 1.690 4.570 ;
    END
  END a2
  PIN vdd
    DIRECTION INOUT ;
    USE POWER ;
    SHAPE ABUTMENT ;
    PORT
      LAYER Metal1 ;
        RECT 1.350 6.330 1.690 6.560 ;
        RECT 6.150 6.330 6.490 6.560 ;
        RECT 1.405 6.560 1.635 7.610 ;
        RECT 6.205 6.560 6.435 7.610 ;
        RECT 0.000 7.610 8.400 8.070 ;
    END
  END vdd
  PIN vss
    DIRECTION INOUT ;
    USE GROUND ;
    SHAPE ABUTMENT ;
    PORT
      LAYER Metal1 ;
        RECT 0.000 -0.230 8.400 0.230 ;
        RECT 1.405 0.230 1.635 1.280 ;
        RECT 6.205 0.230 6.435 1.280 ;
        RECT 1.350 1.280 1.690 1.510 ;
        RECT 6.150 1.280 6.490 1.510 ;
    END
  END vss
  PIN zn
    DIRECTION OUTPUT ;
    USE SIGNAL ;
    ANTENNADIFFAREA 1.408000 ;
    PORT
      LAYER Metal1 ;
        RECT 0.150 1.280 0.490 1.510 ;
        RECT 0.205 1.510 0.435 5.290 ;
        RECT 0.150 5.290 0.490 5.520 ;
    END
  END zn
  OBS
    LAYER Metal1 ;
      RECT 2.005 0.460 3.435 0.690 ;
      RECT 6.750 0.460 7.090 0.690 ;
      RECT 2.005 0.690 2.235 2.540 ;
      RECT 3.205 0.690 3.435 1.280 ;
      RECT 6.805 0.690 7.035 1.280 ;
      RECT 2.550 1.280 2.890 1.510 ;
      RECT 3.205 1.280 4.090 1.510 ;
      RECT 4.950 1.280 5.835 1.510 ;
      RECT 6.805 1.280 7.690 1.510 ;
      RECT 2.605 1.510 2.835 2.540 ;
      RECT 5.605 1.510 5.835 3.140 ;
      RECT 7.405 1.510 7.635 6.330 ;
      RECT 0.750 2.540 2.235 2.770 ;
      RECT 2.605 2.540 5.290 2.770 ;
      RECT 2.605 2.770 2.835 3.140 ;
      RECT 2.005 3.140 2.835 3.370 ;
      RECT 4.405 3.140 5.835 3.370 ;
      RECT 2.005 3.370 2.235 5.290 ;
      RECT 4.405 3.370 4.635 6.330 ;
      RECT 2.550 3.740 3.435 3.970 ;
      RECT 3.205 3.970 3.435 6.330 ;
      RECT 2.005 5.290 2.890 5.520 ;
      RECT 2.550 6.330 2.890 6.560 ;
      RECT 3.205 6.330 4.090 6.560 ;
      RECT 4.405 6.330 5.290 6.560 ;
      RECT 7.350 6.330 7.690 6.560 ;
      RECT 2.605 6.560 2.835 7.150 ;
      RECT 2.550 7.150 2.890 7.380 ;
  END
END gf180mcuf_XNR2D1

MACRO gf180mcuf_MUX2D1
  CLASS CORE ;
  FOREIGN gf180mcuf_MUX2D1 ;
  ORIGIN 0.000 0.000 ;
  SIZE 9.520 BY 7.840 ;
  SYMMETRY X Y R90 ;
  SITE obssite ;
  PIN i0
    DIRECTION INPUT ;
    USE SIGNAL ;
    ANTENNAGATEAREA 0.484400 ;
    PORT
      LAYER Poly2 ;
        RECT 4.380 0.995 4.660 2.475 ;
        RECT 4.340 2.475 4.700 2.835 ;
        RECT 4.380 5.250 4.660 7.085 ;
        RECT 4.340 7.085 4.700 7.445 ;
      LAYER Metal1 ;
        RECT 4.350 2.540 4.690 2.770 ;
        RECT 4.405 2.770 4.635 7.150 ;
        RECT 4.350 7.150 4.690 7.380 ;
    END
  END i0
  PIN i1
    DIRECTION INPUT ;
    USE SIGNAL ;
    ANTENNAGATEAREA 0.616000 ;
    PORT
      LAYER Poly2 ;
        RECT 0.780 0.995 1.060 2.475 ;
        RECT 0.740 2.475 1.100 2.835 ;
        RECT 0.780 2.835 1.060 6.845 ;
      LAYER Metal1 ;
        RECT 0.750 2.540 1.090 2.770 ;
        RECT 0.805 2.770 1.035 3.370 ;
    END
  END i1
  PIN s
    DIRECTION INPUT ;
    USE SIGNAL ;
    ANTENNAGATEAREA 0.616000 ;
    PORT
      LAYER Poly2 ;
        RECT 1.980 0.995 2.260 4.315 ;
        RECT 5.580 0.995 5.860 3.715 ;
        RECT 3.180 3.715 5.860 3.995 ;
        RECT 3.180 3.995 3.460 4.275 ;
        RECT 3.140 4.275 3.500 4.315 ;
        RECT 1.980 4.315 5.860 4.595 ;
        RECT 3.140 4.595 3.500 4.635 ;
        RECT 5.580 4.595 5.860 6.845 ;
        RECT 3.180 4.635 3.460 6.845 ;
      LAYER Metal1 ;
        RECT 3.150 4.340 3.490 4.570 ;
        RECT 3.205 4.570 3.435 5.520 ;
    END
  END s
  PIN vdd
    DIRECTION INOUT ;
    USE POWER ;
    SHAPE ABUTMENT ;
    PORT
      LAYER Metal1 ;
        RECT 0.150 6.330 0.490 6.560 ;
        RECT 4.950 6.330 5.290 6.560 ;
        RECT 8.550 6.330 8.890 6.560 ;
        RECT 0.205 6.560 0.435 7.610 ;
        RECT 5.005 6.560 5.235 7.610 ;
        RECT 8.605 6.560 8.835 7.610 ;
        RECT 0.000 7.610 9.520 8.070 ;
    END
  END vdd
  PIN vss
    DIRECTION INOUT ;
    USE GROUND ;
    SHAPE ABUTMENT ;
    PORT
      LAYER Metal1 ;
        RECT 0.000 -0.230 9.520 0.230 ;
        RECT 0.205 0.230 0.435 1.280 ;
        RECT 5.005 0.230 5.235 1.280 ;
        RECT 8.605 0.230 8.835 1.280 ;
        RECT 0.150 1.280 0.490 1.510 ;
        RECT 4.950 1.280 5.290 1.510 ;
        RECT 8.550 1.280 8.890 1.510 ;
    END
  END vss
  PIN z
    DIRECTION OUTPUT ;
    USE SIGNAL ;
    ANTENNADIFFAREA 1.139200 ;
    PORT
      LAYER Metal1 ;
        RECT 7.350 1.280 7.690 1.510 ;
        RECT 7.405 1.510 7.635 6.330 ;
        RECT 7.350 6.330 7.690 6.560 ;
    END
  END z
  OBS
    LAYER Metal1 ;
      RECT 2.550 0.460 2.890 0.690 ;
      RECT 2.605 0.690 2.835 1.280 ;
      RECT 1.350 1.280 1.690 1.510 ;
      RECT 2.005 1.280 2.890 1.510 ;
      RECT 3.750 1.280 4.090 1.510 ;
      RECT 5.605 1.280 6.490 1.510 ;
      RECT 1.405 1.510 1.635 5.290 ;
      RECT 2.005 1.510 2.235 6.330 ;
      RECT 3.805 1.510 4.035 6.330 ;
      RECT 5.605 1.510 5.835 3.140 ;
      RECT 2.605 3.140 3.490 3.370 ;
      RECT 4.950 3.140 5.835 3.370 ;
      RECT 2.605 3.370 2.835 5.290 ;
      RECT 5.005 3.370 5.235 5.290 ;
      RECT 1.350 5.290 1.690 5.520 ;
      RECT 2.550 5.290 2.890 5.520 ;
      RECT 5.005 5.290 6.435 5.520 ;
      RECT 6.205 5.520 6.435 6.330 ;
      RECT 2.005 6.330 2.890 6.560 ;
      RECT 3.750 6.330 4.090 6.560 ;
      RECT 6.150 6.330 6.490 6.560 ;
  END
END gf180mcuf_MUX2D1

MACRO gf180mcuf_DFQD1
  CLASS CORE ;
  FOREIGN gf180mcuf_DFQD1 ;
  ORIGIN 0.000 0.000 ;
  SIZE 17.920 BY 7.840 ;
  SYMMETRY X Y R90 ;
  SITE obssite ;
  PIN cp
    DIRECTION INPUT ;
    USE SIGNAL ;
    ANTENNAGATEAREA 0.616000 ;
    PORT
      LAYER Poly2 ;
        RECT 0.780 0.995 1.060 2.475 ;
        RECT 0.740 2.475 1.100 2.835 ;
        RECT 0.780 2.835 1.060 6.845 ;
      LAYER Metal1 ;
        RECT 0.805 1.280 1.035 2.540 ;
        RECT 0.750 2.540 1.090 2.770 ;
    END
  END cp
  PIN d
    DIRECTION INPUT ;
    USE SIGNAL ;
    ANTENNAGATEAREA 0.375200 ;
    PORT
      LAYER Poly2 ;
        RECT 5.580 0.995 5.860 2.475 ;
        RECT 5.540 2.475 5.900 2.835 ;
        RECT 5.580 2.835 5.860 6.845 ;
      LAYER Metal1 ;
        RECT 5.605 1.280 5.835 2.540 ;
        RECT 5.550 2.540 5.890 2.770 ;
    END
  END d
  PIN q
    DIRECTION OUTPUT ;
    USE SIGNAL ;
    ANTENNADIFFAREA 1.408000 ;
    PORT
      LAYER Metal1 ;
        RECT 15.750 1.280 16.090 1.510 ;
        RECT 15.805 1.510 16.035 5.290 ;
        RECT 15.750 5.290 16.090 5.520 ;
    END
  END q
  PIN vdd
    DIRECTION INOUT ;
    USE POWER ;
    SHAPE ABUTMENT ;
    PORT
      LAYER Metal1 ;
        RECT 1.350 6.330 1.690 6.560 ;
        RECT 3.750 6.330 4.090 6.560 ;
        RECT 8.550 6.330 8.890 6.560 ;
        RECT 13.350 6.330 13.690 6.560 ;
        RECT 16.950 6.330 17.290 6.560 ;
        RECT 1.405 6.560 1.635 7.610 ;
        RECT 3.805 6.560 4.035 7.610 ;
        RECT 8.605 6.560 8.835 7.610 ;
        RECT 13.405 6.560 13.635 7.610 ;
        RECT 17.005 6.560 17.235 7.610 ;
        RECT 0.000 7.610 17.920 8.070 ;
    END
  END vdd
  PIN vss
    DIRECTION INOUT ;
    USE GROUND ;
    SHAPE ABUTMENT ;
    PORT
      LAYER Metal1 ;
        RECT 0.000 -0.230 17.920 0.230 ;
        RECT 1.405 0.230 1.635 1.280 ;
        RECT 3.805 0.230 4.035 1.280 ;
        RECT 8.605 0.230 8.835 1.280 ;
        RECT 13.405 0.230 13.635 1.280 ;
        RECT 17.005 0.230 17.235 1.280 ;
        RECT 1.350 1.280 1.690 1.510 ;
        RECT 3.750 1.280 4.090 1.510 ;
        RECT 8.550 1.280 8.890 1.510 ;
        RECT 13.350 1.280 13.690 1.510 ;
        RECT 16.950 1.280 17.290 1.510 ;
    END
  END vss
  OBS
    LAYER Metal1 ;
      RECT 11.005 0.460 13.090 0.690 ;
      RECT 11.005 0.690 11.235 1.280 ;
      RECT 0.150 1.280 0.490 1.510 ;
      RECT 2.550 1.280 2.890 1.510 ;
      RECT 6.150 1.280 7.035 1.510 ;
      RECT 9.750 1.280 10.090 1.510 ;
      RECT 10.950 1.280 11.290 1.510 ;
      RECT 14.550 1.280 14.890 1.510 ;
      RECT 0.205 1.510 0.435 3.140 ;
      RECT 2.605 1.510 2.835 2.540 ;
      RECT 6.805 1.510 7.035 2.540 ;
      RECT 9.805 1.510 10.035 4.340 ;
      RECT 11.005 1.510 11.235 6.330 ;
      RECT 14.605 1.510 14.835 2.540 ;
      RECT 2.550 2.540 2.890 2.770 ;
      RECT 6.805 2.540 8.890 2.770 ;
      RECT 12.750 2.540 14.890 2.770 ;
      RECT 14.605 2.770 14.835 5.290 ;
      RECT 0.205 3.140 9.490 3.370 ;
      RECT 0.205 3.370 0.435 3.740 ;
      RECT 0.205 3.740 7.035 3.970 ;
      RECT 0.805 3.970 1.035 5.290 ;
      RECT 6.805 3.970 7.035 5.290 ;
      RECT 2.550 4.340 6.490 4.570 ;
      RECT 7.950 4.340 10.035 4.570 ;
      RECT 2.605 4.570 2.835 5.290 ;
      RECT 3.805 4.570 4.035 5.290 ;
      RECT 9.205 4.570 9.435 6.330 ;
      RECT 0.150 5.290 1.035 5.520 ;
      RECT 2.550 5.290 4.035 5.520 ;
      RECT 6.750 5.290 7.090 5.520 ;
      RECT 8.005 5.290 8.890 5.520 ;
      RECT 14.550 5.290 14.890 5.520 ;
      RECT 8.005 5.520 8.235 7.150 ;
      RECT 6.150 6.330 6.490 6.560 ;
      RECT 9.205 6.330 10.090 6.560 ;
      RECT 10.950 6.330 11.290 6.560 ;
      RECT 6.205 6.560 6.435 7.150 ;
      RECT 6.205 7.150 8.235 7.380 ;
  END
END gf180mcuf_DFQD1

MACRO gf180mcuf_DFCNQD1
  CLASS CORE ;
  FOREIGN gf180mcuf_DFCNQD1 ;
  ORIGIN 0.000 0.000 ;
  SIZE 21.280 BY 7.840 ;
  SYMMETRY X Y R90 ;
  SITE obssite ;
  PIN cdn
    DIRECTION INPUT ;
    USE SIGNAL ;
    ANTENNAGATEAREA 0.754600 ;
    PORT
      LAYER Poly2 ;
        RECT 9.180 0.995 9.460 2.515 ;
        RECT 16.380 0.995 16.660 2.475 ;
        RECT 10.340 2.475 10.700 2.515 ;
        RECT 12.140 2.475 12.500 2.515 ;
        RECT 16.340 2.475 16.700 2.835 ;
        RECT 9.180 2.515 12.500 2.795 ;
        RECT 10.340 2.795 10.700 2.835 ;
        RECT 12.140 2.795 12.500 2.835 ;
        RECT 16.380 2.835 16.660 6.845 ;
        RECT 10.340 5.225 10.700 5.585 ;
        RECT 10.380 5.585 10.660 6.845 ;
      LAYER Metal1 ;
        RECT 10.350 2.540 10.690 2.770 ;
        RECT 12.150 2.540 16.690 2.770 ;
        RECT 10.405 2.770 10.635 5.290 ;
        RECT 10.350 5.290 10.690 5.520 ;
    END
  END cdn
  PIN cp
    DIRECTION INPUT ;
    USE SIGNAL ;
    ANTENNAGATEAREA 0.308000 ;
    PORT
      LAYER Poly2 ;
        RECT 0.740 0.395 1.100 0.755 ;
        RECT 0.780 0.755 1.060 1.835 ;
        RECT 0.740 3.075 1.100 3.435 ;
        RECT 0.780 3.435 1.060 6.845 ;
      LAYER Metal1 ;
        RECT 0.750 0.460 1.090 0.690 ;
        RECT 0.805 0.690 1.035 3.140 ;
        RECT 0.750 3.140 1.090 3.370 ;
    END
  END cp
  PIN d
    DIRECTION INPUT ;
    USE SIGNAL ;
    ANTENNAGATEAREA 0.400400 ;
    PORT
      LAYER Poly2 ;
        RECT 5.580 0.995 5.860 2.475 ;
        RECT 5.540 2.475 5.900 2.835 ;
        RECT 5.540 4.275 5.900 4.635 ;
        RECT 5.580 4.635 5.860 6.845 ;
      LAYER Metal1 ;
        RECT 5.550 2.540 5.890 2.770 ;
        RECT 5.605 2.770 5.835 4.340 ;
        RECT 5.550 4.340 5.890 4.570 ;
    END
  END d
  PIN q
    DIRECTION OUTPUT ;
    USE SIGNAL ;
    ANTENNADIFFAREA 1.408000 ;
    PORT
      LAYER Metal1 ;
        RECT 20.550 1.280 20.890 1.510 ;
        RECT 20.605 1.510 20.835 5.290 ;
        RECT 19.350 5.290 20.835 5.520 ;
    END
  END q
  PIN vdd
    DIRECTION INOUT ;
    USE POWER ;
    SHAPE ABUTMENT ;
    PORT
      LAYER Metal1 ;
        RECT 1.350 6.330 1.690 6.560 ;
        RECT 3.750 6.330 4.090 6.560 ;
        RECT 8.550 6.330 8.890 6.560 ;
        RECT 10.950 6.330 11.290 6.560 ;
        RECT 15.750 6.330 16.090 6.560 ;
        RECT 18.150 6.330 18.490 6.560 ;
        RECT 1.405 6.560 1.635 7.610 ;
        RECT 3.805 6.560 4.035 7.610 ;
        RECT 8.605 6.560 8.835 7.610 ;
        RECT 11.005 6.560 11.235 7.610 ;
        RECT 15.805 6.560 16.035 7.610 ;
        RECT 18.205 6.560 18.435 7.610 ;
        RECT 0.000 7.610 21.280 8.070 ;
    END
  END vdd
  PIN vss
    DIRECTION INOUT ;
    USE GROUND ;
    SHAPE ABUTMENT ;
    PORT
      LAYER Metal1 ;
        RECT 0.000 -0.230 21.280 0.230 ;
        RECT 1.405 0.230 1.635 1.280 ;
        RECT 3.805 0.230 4.035 1.280 ;
        RECT 9.805 0.230 10.035 1.280 ;
        RECT 15.805 0.230 16.035 1.280 ;
        RECT 19.405 0.230 19.635 1.280 ;
        RECT 1.350 1.280 1.690 1.510 ;
        RECT 3.750 1.280 4.090 1.510 ;
        RECT 9.750 1.280 10.090 1.510 ;
        RECT 15.750 1.280 16.090 1.510 ;
        RECT 19.350 1.280 19.690 1.510 ;
    END
  END vss
  OBS
    LAYER Metal1 ;
      RECT 2.550 0.460 2.890 0.690 ;
      RECT 6.205 0.460 9.490 0.690 ;
      RECT 10.350 0.460 11.835 0.690 ;
      RECT 12.205 0.460 15.490 0.690 ;
      RECT 2.605 0.690 2.835 1.280 ;
      RECT 6.205 0.690 6.435 1.280 ;
      RECT 11.605 0.690 11.835 3.740 ;
      RECT 12.205 0.690 12.435 1.280 ;
      RECT 0.150 1.280 0.490 1.510 ;
      RECT 2.550 1.280 2.890 1.510 ;
      RECT 6.150 1.280 6.490 1.510 ;
      RECT 10.950 1.280 11.290 1.510 ;
      RECT 12.150 1.280 12.490 1.510 ;
      RECT 13.350 1.280 14.890 1.510 ;
      RECT 18.150 1.280 18.490 1.510 ;
      RECT 0.205 1.510 0.435 2.540 ;
      RECT 2.605 1.510 2.835 6.330 ;
      RECT 6.205 1.510 6.435 6.330 ;
      RECT 11.005 1.510 11.235 3.740 ;
      RECT 18.205 1.510 18.435 2.540 ;
      RECT 0.150 2.540 0.490 2.770 ;
      RECT 7.950 2.540 8.290 2.770 ;
      RECT 18.205 2.540 20.290 2.770 ;
      RECT 8.005 2.770 8.235 3.740 ;
      RECT 18.805 2.770 19.035 4.340 ;
      RECT 6.750 3.140 7.090 3.370 ;
      RECT 6.805 3.370 7.035 5.290 ;
      RECT 7.950 3.740 8.290 3.970 ;
      RECT 10.950 3.740 11.290 3.970 ;
      RECT 11.550 3.740 11.890 3.970 ;
      RECT 8.005 3.970 8.235 4.340 ;
      RECT 11.005 3.970 11.235 5.290 ;
      RECT 7.950 4.340 8.290 4.570 ;
      RECT 14.005 4.340 17.890 4.570 ;
      RECT 18.750 4.340 19.090 4.570 ;
      RECT 14.005 4.570 14.235 6.330 ;
      RECT 0.205 5.290 1.690 5.520 ;
      RECT 6.750 5.290 7.090 5.520 ;
      RECT 7.405 5.290 10.035 5.520 ;
      RECT 11.005 5.290 12.435 5.520 ;
      RECT 15.150 5.290 17.235 5.520 ;
      RECT 0.205 5.520 0.435 6.330 ;
      RECT 7.405 5.520 7.635 6.330 ;
      RECT 9.805 5.520 10.035 6.330 ;
      RECT 12.205 5.520 12.435 6.330 ;
      RECT 17.005 5.520 17.235 6.330 ;
      RECT 0.150 6.330 0.490 6.560 ;
      RECT 2.550 6.330 2.890 6.560 ;
      RECT 6.150 6.330 6.490 6.560 ;
      RECT 7.350 6.330 7.690 6.560 ;
      RECT 9.750 6.330 10.090 6.560 ;
      RECT 12.150 6.330 12.490 6.560 ;
      RECT 13.350 6.330 14.235 6.560 ;
      RECT 16.950 6.330 17.290 6.560 ;
      RECT 2.605 6.560 2.835 7.150 ;
      RECT 2.550 7.150 2.890 7.380 ;
  END
END gf180mcuf_DFCNQD1

MACRO gf180mcuf_TIEH
  CLASS CORE TIEHIGH ;
  FOREIGN gf180mcuf_TIEH ;
  ORIGIN 0.000 0.000 ;
  SIZE 2.240 BY 7.840 ;
  SYMMETRY X Y R90 ;
  SITE obssite ;
  PIN vdd
    DIRECTION INOUT ;
    USE POWER ;
    SHAPE ABUTMENT ;
    PORT
      LAYER Metal1 ;
        RECT 1.350 6.330 1.690 6.560 ;
        RECT 1.405 6.560 1.635 7.610 ;
        RECT 0.000 7.610 2.240 8.070 ;
    END
  END vdd
  PIN vss
    DIRECTION INOUT ;
    USE GROUND ;
    SHAPE ABUTMENT ;
    PORT
      LAYER Metal1 ;
        RECT 0.000 -0.230 2.240 0.230 ;
        RECT 1.405 0.230 1.635 1.280 ;
        RECT 1.350 1.280 1.690 1.510 ;
    END
  END vss
  PIN z
    DIRECTION OUTPUT ;
    USE SIGNAL ;
    ANTENNADIFFAREA 0.896000 ;
    PORT
      LAYER Metal1 ;
        RECT 0.205 5.290 0.435 6.330 ;
        RECT 0.150 6.330 0.490 6.560 ;
        RECT 0.205 6.560 0.435 7.380 ;
    END
  END z
  OBS
    LAYER Metal1 ;
      RECT 0.750 0.460 1.090 0.690 ;
      RECT 0.805 0.690 1.035 1.280 ;
      RECT 0.150 1.280 1.035 1.510 ;
  END
END gf180mcuf_TIEH

MACRO gf180mcuf_TIEL
  CLASS CORE TIELOW ;
  FOREIGN gf180mcuf_TIEL ;
  ORIGIN 0.000 0.000 ;
  SIZE 2.240 BY 7.840 ;
  SYMMETRY X Y R90 ;
  SITE obssite ;
  PIN vdd
    DIRECTION INOUT ;
    USE POWER ;
    SHAPE ABUTMENT ;
    PORT
      LAYER Metal1 ;
        RECT 1.350 6.330 1.690 6.560 ;
        RECT 1.405 6.560 1.635 7.610 ;
        RECT 0.000 7.610 2.240 8.070 ;
    END
  END vdd
  PIN vss
    DIRECTION INOUT ;
    USE GROUND ;
    SHAPE ABUTMENT ;
    PORT
      LAYER Metal1 ;
        RECT 0.000 -0.230 2.240 0.230 ;
        RECT 1.405 0.230 1.635 1.280 ;
        RECT 1.350 1.280 1.690 1.510 ;
    END
  END vss
  PIN zn
    DIRECTION OUTPUT ;
    USE SIGNAL ;
    ANTENNADIFFAREA 0.512000 ;
    PORT
      LAYER Metal1 ;
        RECT 0.150 1.280 1.035 1.510 ;
        RECT 0.805 1.510 1.035 2.770 ;
    END
  END zn
  OBS
    LAYER Metal1 ;
      RECT 0.150 4.340 0.490 4.570 ;
      RECT 0.205 4.570 0.435 5.290 ;
      RECT 0.150 5.290 0.490 5.520 ;
  END
END gf180mcuf_TIEL

MACRO gf180mcuf_FILL1
  CLASS CORE SPACER ;
  FOREIGN gf180mcuf_FILL1 ;
  ORIGIN 0.000 0.000 ;
  SIZE 0.560 BY 7.840 ;
  SYMMETRY X Y R90 ;
  SITE obssite ;
  PIN vdd
    DIRECTION INOUT ;
    USE POWER ;
    SHAPE ABUTMENT ;
    PORT
      LAYER Metal1 ;
        RECT 0.000 7.610 0.560 8.070 ;
    END
  END vdd
  PIN vss
    DIRECTION INOUT ;
    USE GROUND ;
    SHAPE ABUTMENT ;
    PORT
      LAYER Metal1 ;
        RECT 0.000 -0.230 0.560 0.230 ;
    END
  END vss
END gf180mcuf_FILL1

MACRO gf180mcuf_FILL2
  CLASS CORE SPACER ;
  FOREIGN gf180mcuf_FILL2 ;
  ORIGIN 0.000 0.000 ;
  SIZE 1.120 BY 7.840 ;
  SYMMETRY X Y R90 ;
  SITE obssite ;
  PIN vdd
    DIRECTION INOUT ;
    USE POWER ;
    SHAPE ABUTMENT ;
    PORT
      LAYER Metal1 ;
        RECT 0.000 7.610 1.120 8.070 ;
    END
  END vdd
  PIN vss
    DIRECTION INOUT ;
    USE GROUND ;
    SHAPE ABUTMENT ;
    PORT
      LAYER Metal1 ;
        RECT 0.000 -0.230 1.120 0.230 ;
    END
  END vss
END gf180mcuf_FILL2

MACRO gf180mcuf_FILL4
  CLASS CORE SPACER ;
  FOREIGN gf180mcuf_FILL4 ;
  ORIGIN 0.000 0.000 ;
  SIZE 2.240 BY 7.840 ;
  SYMMETRY X Y R90 ;
  SITE obssite ;
  PIN vdd
    DIRECTION INOUT ;
    USE POWER ;
    SHAPE ABUTMENT ;
    PORT
      LAYER Metal1 ;
        RECT 0.000 7.610 2.240 8.070 ;
    END
  END vdd
  PIN vss
    DIRECTION INOUT ;
    USE GROUND ;
    SHAPE ABUTMENT ;
    PORT
      LAYER Metal1 ;
        RECT 0.000 -0.230 2.240 0.230 ;
    END
  END vss
END gf180mcuf_FILL4

MACRO gf180mcuf_FILL8
  CLASS CORE SPACER ;
  FOREIGN gf180mcuf_FILL8 ;
  ORIGIN 0.000 0.000 ;
  SIZE 4.480 BY 7.840 ;
  SYMMETRY X Y R90 ;
  SITE obssite ;
  PIN vdd
    DIRECTION INOUT ;
    USE POWER ;
    SHAPE ABUTMENT ;
    PORT
      LAYER Metal1 ;
        RECT 0.000 7.610 4.480 8.070 ;
    END
  END vdd
  PIN vss
    DIRECTION INOUT ;
    USE GROUND ;
    SHAPE ABUTMENT ;
    PORT
      LAYER Metal1 ;
        RECT 0.000 -0.230 4.480 0.230 ;
    END
  END vss
END gf180mcuf_FILL8

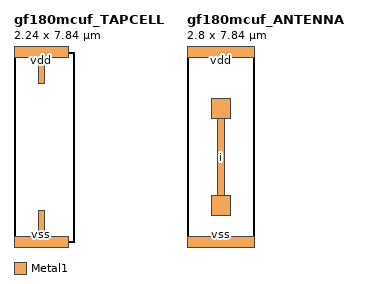
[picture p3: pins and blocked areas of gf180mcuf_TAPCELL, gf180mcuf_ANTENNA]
MACRO gf180mcuf_TAPCELL
  CLASS CORE WELLTAP ;
  FOREIGN gf180mcuf_TAPCELL ;
  ORIGIN 0.000 0.000 ;
  SIZE 2.240 BY 7.840 ;
  SYMMETRY X Y R90 ;
  SITE obssite ;
  PIN vdd
    DIRECTION INOUT ;
    USE POWER ;
    SHAPE ABUTMENT ;
    PORT
      LAYER Metal1 ;
        RECT 1.000 6.550 1.240 7.610 ;
        RECT 0.000 7.610 2.240 8.070 ;
    END
  END vdd
  PIN vss
    DIRECTION INOUT ;
    USE GROUND ;
    SHAPE ABUTMENT ;
    PORT
      LAYER Metal1 ;
        RECT 0.000 -0.230 2.240 0.230 ;
        RECT 1.000 0.230 1.240 1.290 ;
    END
  END vss
END gf180mcuf_TAPCELL

MACRO gf180mcuf_ANTENNA
  CLASS CORE ANTENNACELL ;
  FOREIGN gf180mcuf_ANTENNA ;
  ORIGIN 0.000 0.000 ;
  SIZE 2.800 BY 7.840 ;
  SYMMETRY X Y R90 ;
  SITE obssite ;
  PIN i
    DIRECTION INPUT ;
    USE SIGNAL ;
    PORT
      LAYER Metal1 ;
        RECT 0.995 1.095 1.805 1.905 ;
        RECT 1.250 1.905 1.550 5.095 ;
        RECT 0.995 5.095 1.805 5.905 ;
    END
  END i
  PIN vdd
    DIRECTION INOUT ;
    USE POWER ;
    SHAPE ABUTMENT ;
    PORT
      LAYER Metal1 ;
        RECT 0.000 7.610 2.800 8.070 ;
    END
  END vdd
  PIN vss
    DIRECTION INOUT ;
    USE GROUND ;
    SHAPE ABUTMENT ;
    PORT
      LAYER Metal1 ;
        RECT 0.000 -0.230 2.800 0.230 ;
    END
  END vss
END gf180mcuf_ANTENNA

END LIBRARY
